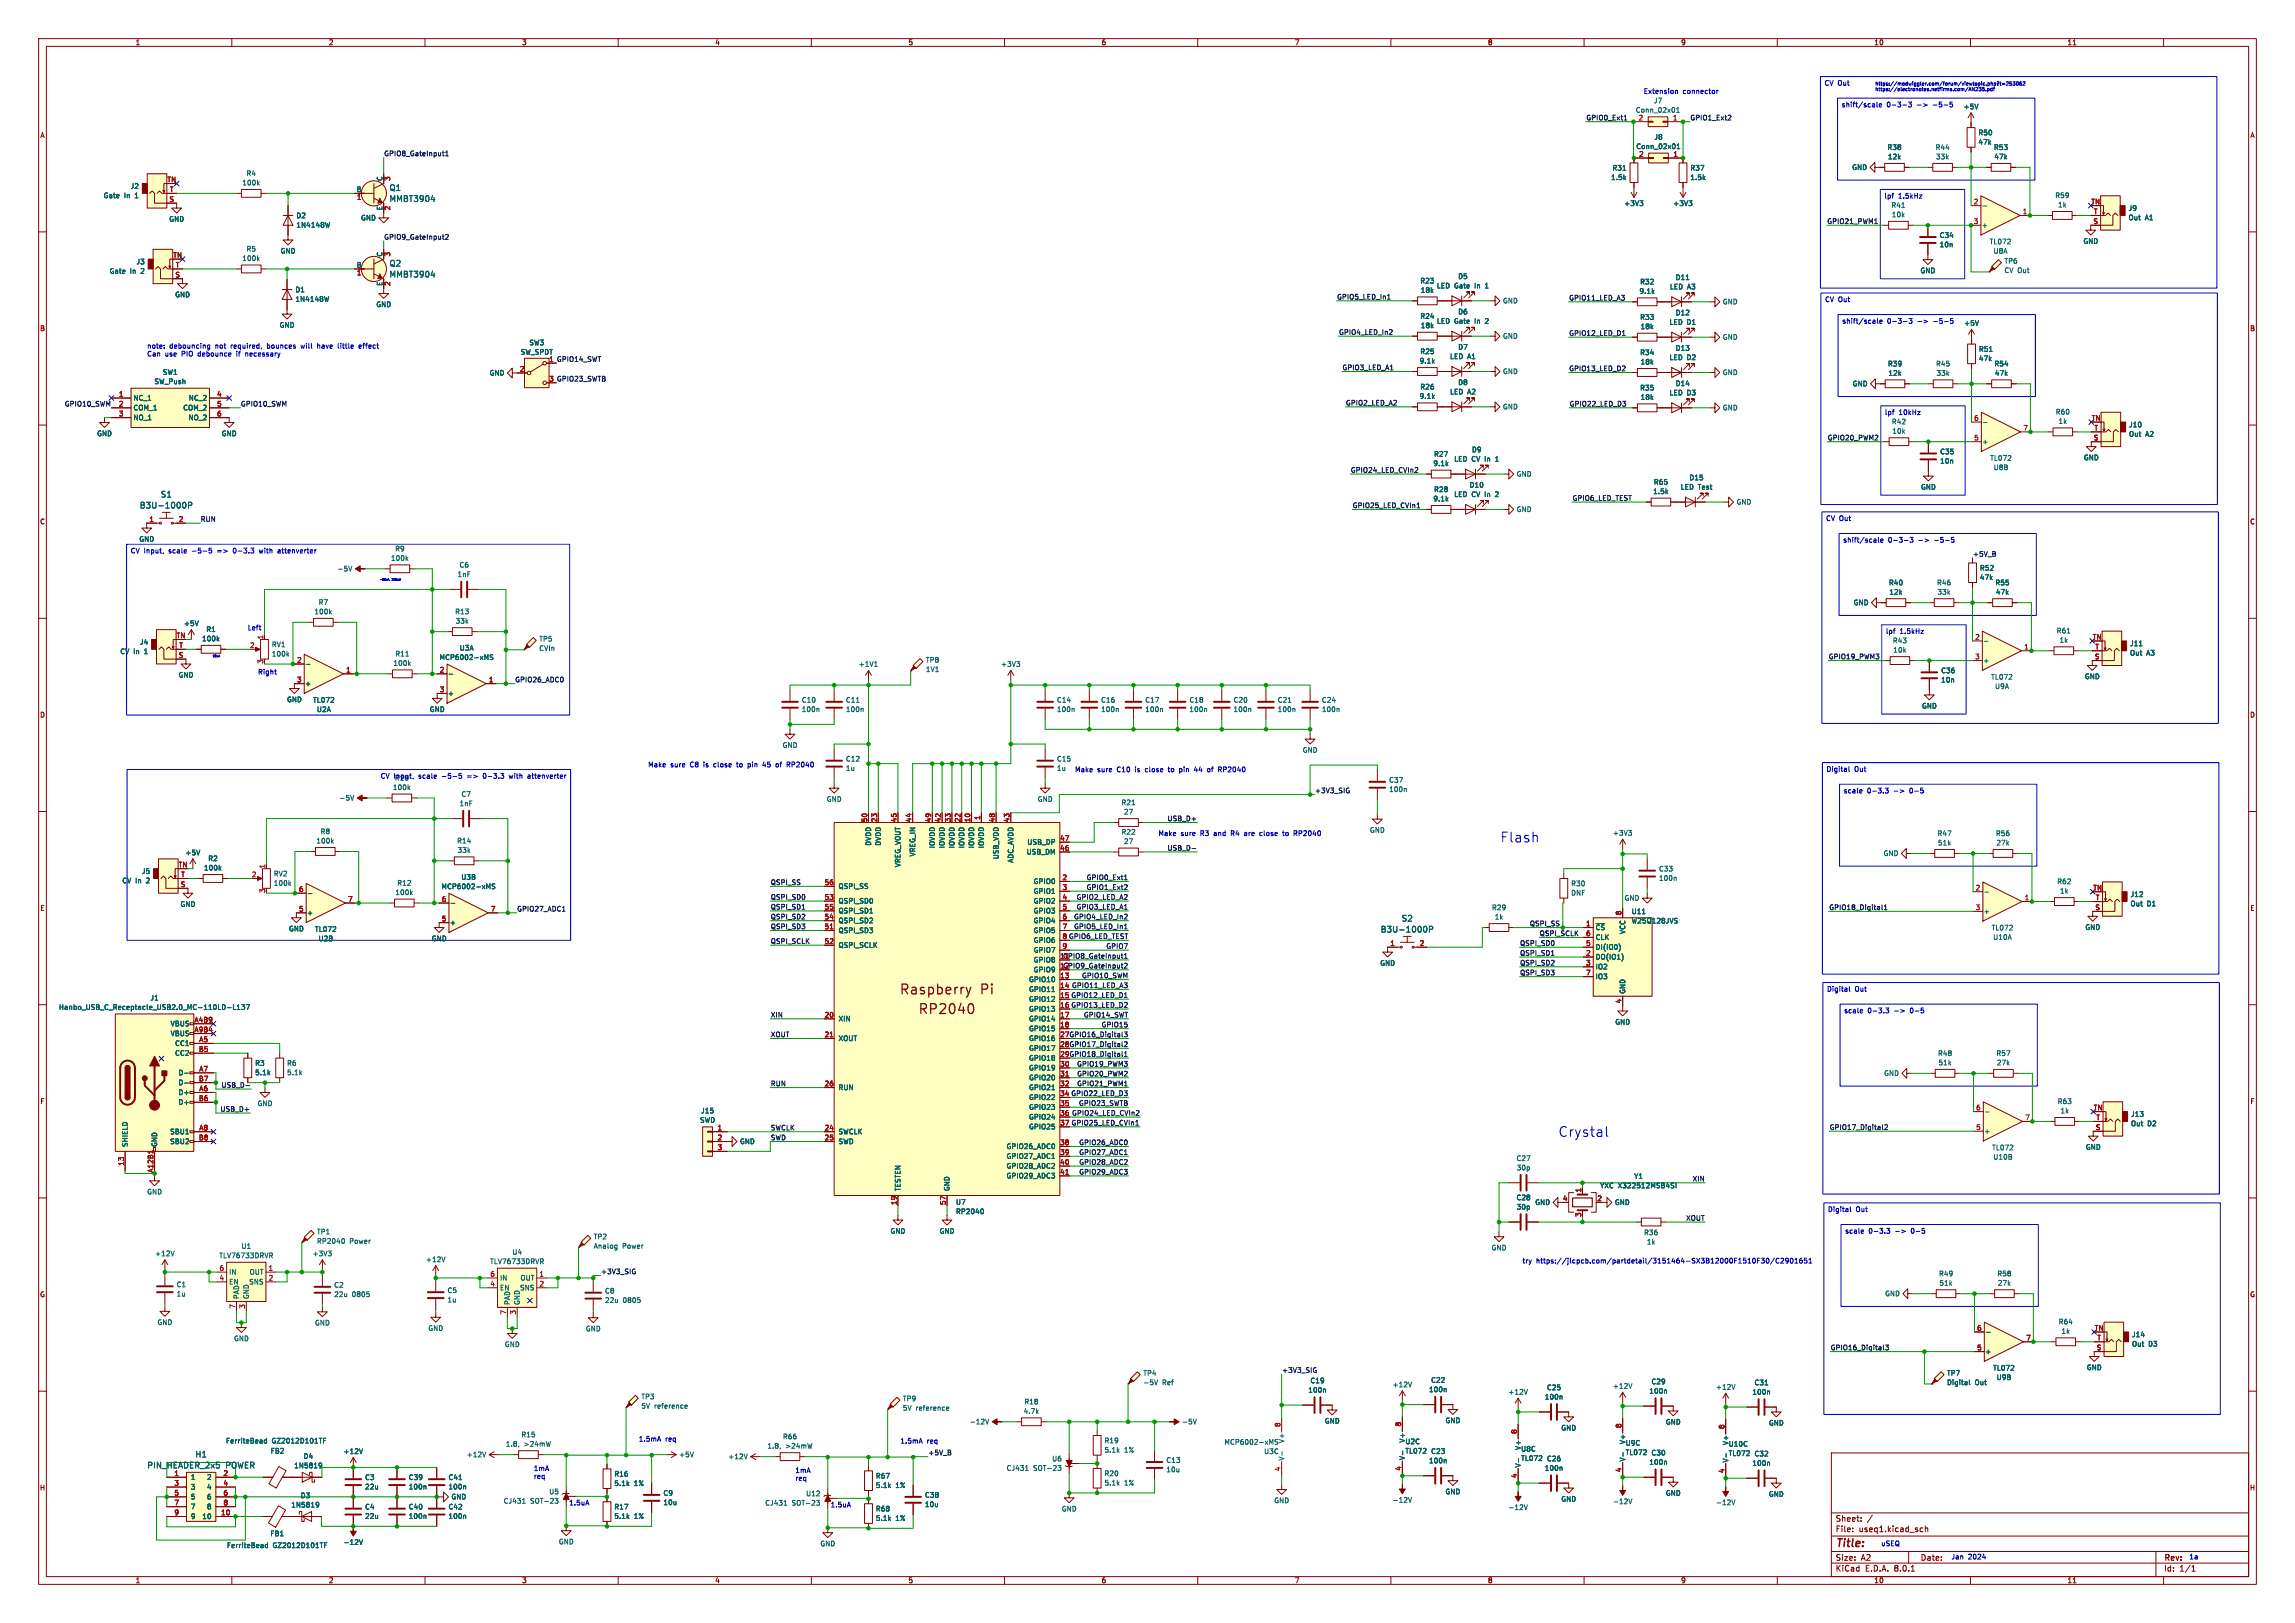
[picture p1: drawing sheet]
<svg xmlns="http://www.w3.org/2000/svg" width="594mm" height="420mm" viewBox="0 0 594 420" stroke-linecap="round" stroke-linejoin="round" font-family="sans-serif">
<defs><g id="words">
<g font-size="3.5" fill="#0000c2">
<text x="388.2" y="218.2">Flash</text>
<text x="403.2" y="294.4">Crystal</text>
</g>
<g font-size="3.5" fill="#840000">
<text x="232.7" y="257.8">Raspberry</text>
<text x="253.8" y="257.8">Pi</text>
<text x="237.5" y="262.9">RP2040</text>
</g>
<text font-size="2.8" fill="#840000" x="475" y="400.9">Title:</text>
<g font-size="2.1" fill="#006464">
<text x="100.7" y="49.6">Q1</text>
<text x="100.7" y="52.4">MMBT3904</text>
<text x="100.7" y="69.2">Q2</text>
<text x="100.7" y="72">MMBT3904</text>
<text x="36.1" y="131.8">B3U-1000P</text>
<text x="41.5" y="128.9">S1</text>
<text x="362.7" y="238.7">S2</text>
<text x="357.3" y="241.5">B3U-1000P</text>
<text x="50.5" y="377.4">H1</text>
<text x="38" y="380.2">PIN_HEADER_2x5</text>
<text x="58.4" y="380.2">POWER</text>
</g>
<g font-size="2.1" fill="#840000">
<text x="475" y="394">Sheet:</text>
<text x="475" y="396.7">File:</text>
<text x="481.1" y="396.7">useq1.kicad_sch</text>
<text x="475" y="406.9">KiCad</text>
<text x="475" y="404.1">Size:</text>
<text x="481.7" y="404.1">A2</text>
<text x="482.7" y="406.9">E.D.A.</text>
<text x="490.3" y="406.9">8.0.1</text>
<text x="497" y="404.1">Date:</text>
<text x="560" y="404.3">Rev:</text>
<text x="560" y="406.9">Id:</text>
<text x="564.1" y="406.9">1/1</text>
</g>
<g font-size="1.8" fill="#840000">
<text x="35" y="11.9">1</text>
<text x="85" y="11.9">2</text>
<text x="135" y="11.9">3</text>
<text x="185" y="11.9">4</text>
<text x="235" y="11.9">5</text>
<text x="285" y="11.9">6</text>
<text x="335" y="11.9">7</text>
<text x="385" y="11.9">8</text>
<text x="435" y="11.9">9</text>
<text x="485" y="11.9">10</text>
<text x="535" y="11.9">11</text>
<text x="10.3" y="35.9">A</text>
<text x="582.3" y="35.9">A</text>
<text x="10.3" y="85.9">B</text>
<text x="582.3" y="85.9">B</text>
<text x="10.3" y="135.9">C</text>
<text x="582.3" y="135.9">C</text>
<text x="10.3" y="185.9">D</text>
<text x="582.3" y="185.9">D</text>
<text x="10.3" y="235.9">E</text>
<text x="582.3" y="235.9">E</text>
<text x="274.3" y="255.8">14 GPIO11_LED_A3</text>
<text x="274.3" y="258.3">15 GPIO12_LED_D1</text>
<text x="274.3" y="260.9">16 GPIO13_LED_D2</text>
<text x="274.3" y="268.5">27 GPIO16_Digital3</text>
<text x="274.3" y="271">28 GPIO17_Digital2</text>
<text x="274.3" y="273.6">29 GPIO18_Digital1</text>
<text x="10.3" y="285.9">F</text>
<text x="274.3" y="283.7">34 GPIO22_LED_D3</text>
<text x="582.3" y="285.9">F</text>
<text x="274.3" y="288.8">36 GPIO24_LED_CVIn2</text>
<text x="274.3" y="291.3">37 GPIO25_LED_CVIn1</text>
<text x="10.3" y="335.9">G</text>
<text x="582.3" y="335.9">G</text>
<text x="10.2" y="385.9">H</text>
<text x="582.2" y="385.9">H</text>
<text x="35" y="409.9">1</text>
<text x="85" y="409.9">2</text>
<text x="135" y="409.9">3</text>
<text x="185" y="409.9">4</text>
<text x="235" y="409.9">5</text>
<text x="285" y="409.9">6</text>
<text x="335" y="409.9">7</text>
<text x="385" y="409.9">8</text>
<text x="435" y="409.9">9</text>
<text x="485" y="409.9">10</text>
<text x="535" y="409.9">11</text>
</g>
<g font-size="1.8" fill="#0000c2">
<text x="472.1" y="22.5">CV Out</text>
<text x="425.3" y="24.4">Extension</text>
<text x="435.6" y="24.4">connector</text>
<text x="476.6" y="28.1">shift/scale</text>
<text x="488.3" y="28.1">0-3-3</text>
<text x="500.6" y="28.1">-5-5</text>
<text x="487.6" y="51.7">lpf</text>
<text x="491.3" y="51.7">1.5kHz</text>
<text x="472.2" y="78.5">CV Out</text>
<text x="476.7" y="84.1">shift/scale</text>
<text x="488.4" y="84.1">0-3-3</text>
<text x="500.7" y="84.1">-5-5</text>
<text x="38" y="90.3">note:</text>
<text x="38" y="92.3">Can</text>
<text x="42.7" y="92.3">use</text>
<text x="43.9" y="90.3">debouncing</text>
<text x="47.1" y="92.3">PIO</text>
<text x="51.5" y="92.3">debounce</text>
<text x="55.9" y="90.3">not</text>
<text x="60.1" y="90.3">required,</text>
<text x="61.7" y="92.3">if</text>
<text x="64.2" y="92.3">necessary</text>
<text x="69.6" y="90.3">bounces</text>
<text x="78.6" y="90.3">will</text>
<text x="83" y="90.3">have</text>
<text x="88.6" y="90.3">little</text>
<text x="94.2" y="90.3">effect</text>
<text x="487.7" y="107.7">lpf</text>
<text x="491.5" y="107.7">10kHz</text>
<text x="472.5" y="135.1">CV Out</text>
<text x="33.7" y="143.5">CV Input,</text>
<text x="43.8" y="143.5">scale</text>
<text x="50" y="143.5">-5-5</text>
<text x="56.7" y="143.5">=&gt;</text>
<text x="61" y="143.5">0-3.3</text>
<text x="68" y="143.5">with</text>
<text x="73" y="143.5">attenverter</text>
<text x="476.9" y="140.7">shift/scale</text>
<text x="488.7" y="140.7">0-3-3</text>
<text x="501" y="140.7">-5-5</text>
<text x="64" y="163.2">Left</text>
<text x="488" y="164.4">lpf</text>
<text x="491.7" y="164.4">1.5kHz</text>
<text x="66.7" y="174.6">Right</text>
<text x="98.4" y="201.8">CV Input,</text>
<text x="102.1" y="202.2">R10</text>
<text x="108.5" y="201.8">scale</text>
<text x="114.7" y="201.8">-5-5</text>
<text x="121.4" y="201.8">=&gt;</text>
<text x="125.7" y="201.8">0-3.3</text>
<text x="132.7" y="201.8">with</text>
<text x="137.7" y="201.8">attenverter</text>
<text x="167.6" y="198.6">Make</text>
<text x="173.5" y="198.6">sure</text>
<text x="178.8" y="198.6">C8</text>
<text x="182.4" y="198.6">is</text>
<text x="185.2" y="198.6">close</text>
<text x="191.4" y="198.6">to</text>
<text x="194.4" y="198.6">pin</text>
<text x="198.5" y="198.6">45</text>
<text x="202.1" y="198.6">of</text>
<text x="205.1" y="198.6">RP2040</text>
<text x="278.1" y="199.9">Make</text>
<text x="284" y="199.9">sure</text>
<text x="289.2" y="199.9">C10</text>
<text x="294.1" y="199.9">is</text>
<text x="296.9" y="199.9">close</text>
<text x="303.1" y="199.9">to</text>
<text x="306.1" y="199.9">pin</text>
<text x="310.2" y="199.9">44</text>
<text x="313.8" y="199.9">of</text>
<text x="316.8" y="199.9">RP2040</text>
<text x="472.6" y="200">Digital</text>
<text x="480" y="200">Out</text>
<text x="477.1" y="205.6">scale</text>
<text x="483.3" y="205.6">0-3.3</text>
<text x="494.6" y="205.6">0-5</text>
<text x="299.7" y="216.4">Make</text>
<text x="305.6" y="216.4">sure</text>
<text x="310.8" y="216.4">R3</text>
<text x="314.5" y="216.4">and</text>
<text x="319.1" y="216.4">R4</text>
<text x="322.8" y="216.4">are</text>
<text x="326.9" y="216.4">close</text>
<text x="333.1" y="216.4">to</text>
<text x="336.2" y="216.4">RP2040</text>
<text x="472.8" y="256.9">Digital</text>
<text x="480.1" y="256.9">Out</text>
<text x="477.2" y="262.5">scale</text>
<text x="483.4" y="262.5">0-3.3</text>
<text x="494.7" y="262.5">0-5</text>
<text x="473" y="314">Digital</text>
<text x="480.3" y="314">Out</text>
<text x="477.5" y="319.5">scale</text>
<text x="483.6" y="319.5">0-3.3</text>
<text x="494.9" y="319.5">0-5</text>
<text x="394" y="327">try</text>
<text x="397.6" y="327">https://jlcpcb.com/partdetail/3151464-SX3B12000F1510F30/C2901651</text>
<text x="165.2" y="373.1">1.5mA</text>
<text x="172.2" y="373.1">req</text>
<text x="232.9" y="373.6">1.5mA</text>
<text x="239.9" y="373.6">req</text>
<text x="138" y="380.7">1mA</text>
<text x="138" y="382.8">req</text>
<text x="205.7" y="381.2">1mA</text>
<text x="205.7" y="383.3">req</text>
<text x="147.2" y="389.6">1.5uA</text>
<text x="214.9" y="390.1">1.5uA</text>
<text x="486.8" y="400.2">uSEQ</text>
<text x="505" y="403.6">Jan</text>
<text x="509.4" y="403.6">2024</text>
<text x="566.5" y="403.6">1a</text>
</g>
<g font-size="1.8" fill="#006464">
<text x="423.3" y="29.4">Conn_02x01</text>
<text x="427.9" y="26.9">J7</text>
<text x="508.1" y="28.5">+5V</text>
<text x="511.9" y="35.2">R50</text>
<text x="423.4" y="38.8">Conn_02x01</text>
<text x="428.1" y="36.3">J8</text>
<text x="488.4" y="39">R38</text>
<text x="488.5" y="41.4">12k</text>
<text x="500.8" y="39">R44</text>
<text x="501" y="41.4">33k</text>
<text x="511.9" y="37.6">47k</text>
<text x="516" y="39">R53</text>
<text x="516.1" y="41.4">47k</text>
<text x="63.7" y="45.7">R4</text>
<text x="99.1" y="47" transform="rotate(-90 99.1 47)">C</text>
<text x="416.9" y="46.8">1.5k</text>
<text x="417.2" y="44.4">R31</text>
<text x="437.4" y="44.4">R37</text>
<text x="437.4" y="46.8">1.5k</text>
<text x="479.3" y="44.2">GND</text>
<text x="26.7" y="51.5">Gate</text>
<text x="32.1" y="51.5">In</text>
<text x="33.7" y="49.1">J2</text>
<text x="35.1" y="51.5">1</text>
<text x="62.6" y="48.2">100k</text>
<text x="92.2" y="49.8">B</text>
<text x="420.3" y="53.5">+3V3</text>
<text x="433" y="53.5">+3V3</text>
<text x="489.4" y="54">R41</text>
<text x="531.8" y="51.5">R59</text>
<text x="532.6" y="53.9">1k</text>
<text x="43.7" y="57.6">GND</text>
<text x="76.6" y="56.7">D2</text>
<text x="76.6" y="59.1">1N4148W</text>
<text x="93.3" y="57.3">GND</text>
<text x="99.1" y="54.5" transform="rotate(-90 99.1 54.5)">E</text>
<text x="489.5" y="56.4">10k</text>
<text x="512.8" y="59.2">+</text>
<text x="550.8" y="54.8">J9</text>
<text x="550.8" y="57.2">Out</text>
<text x="555.2" y="57.2">A1</text>
<text x="63.7" y="65.3">R5</text>
<text x="72.5" y="65.8">GND</text>
<text x="501.9" y="61.8">C34</text>
<text x="501.9" y="64.2">10n</text>
<text x="514.9" y="63.4">TL072</text>
<text x="515.9" y="65.8">U8A</text>
<text x="539.1" y="63.3">GND</text>
<text x="28.2" y="71">Gate</text>
<text x="33.7" y="71">In</text>
<text x="35.2" y="68.6">J3</text>
<text x="36.6" y="71">2</text>
<text x="62.6" y="67.7">100k</text>
<text x="92.2" y="69.3">B</text>
<text x="99.1" y="66.5" transform="rotate(-90 99.1 66.5)">C</text>
<text x="496.9" y="70.9">GND</text>
<text x="518.7" y="68.4">TP6</text>
<text x="518.7" y="70.8">CV Out</text>
<text x="45.2" y="77.1">GND</text>
<text x="76.3" y="75.9">D1</text>
<text x="99.1" y="74.1" transform="rotate(-90 99.1 74.1)">E</text>
<text x="367.5" y="73.6">R23</text>
<text x="367.6" y="76">18k</text>
<text x="371.8" y="74.8">LED Gate</text>
<text x="377.3" y="72.4">D5</text>
<text x="381.8" y="74.8">In</text>
<text x="384.7" y="74.8">1</text>
<text x="424.2" y="76.2">9.1k</text>
<text x="424.4" y="73.8">R32</text>
<text x="432.1" y="75.1">LED A3</text>
<text x="433.6" y="72.7">D11</text>
<text x="76.3" y="78.3">1N4148W</text>
<text x="97.3" y="79.7">GND</text>
<text x="367.5" y="82.7">R24</text>
<text x="371.8" y="84">LED Gate</text>
<text x="377.3" y="81.6">D6</text>
<text x="381.8" y="84">In</text>
<text x="384.7" y="84">2</text>
<text x="388.9" y="78.7">GND</text>
<text x="424.4" y="83">R33</text>
<text x="433.6" y="81.8">D12</text>
<text x="445.8" y="79">GND</text>
<text x="72.3" y="85">GND</text>
<text x="136.9" y="89.6">SW3</text>
<text x="367.6" y="85.1">18k</text>
<text x="388.9" y="87.9">GND</text>
<text x="424.5" y="85.4">18k</text>
<text x="432" y="84.2">LED D1</text>
<text x="445.8" y="88.1">GND</text>
<text x="508.2" y="84.5">+5V</text>
<text x="134.7" y="92">SW_SPDT</text>
<text x="367.3" y="94.3">9.1k</text>
<text x="367.5" y="91.8">R25</text>
<text x="375.2" y="93.1">LED A1</text>
<text x="377.3" y="90.7">D7</text>
<text x="424.4" y="92.1">R34</text>
<text x="424.5" y="94.5">18k</text>
<text x="432" y="93.4">LED D2</text>
<text x="433.6" y="91">D13</text>
<text x="488.5" y="95">R39</text>
<text x="501" y="95">R45</text>
<text x="512.1" y="91.2">R51</text>
<text x="512.1" y="93.6">47k</text>
<text x="516.1" y="95">R54</text>
<text x="39.9" y="99.6">SW_Push</text>
<text x="42" y="97.2">SW1</text>
<text x="126.6" y="97.4">GND</text>
<text x="367.5" y="101">R26</text>
<text x="377.3" y="99.8">D8</text>
<text x="388.9" y="97">GND</text>
<text x="424.4" y="101.2">R35</text>
<text x="433.6" y="100.1">D14</text>
<text x="445.8" y="97.3">GND</text>
<text x="479.4" y="100.2">GND</text>
<text x="488.6" y="97.4">12k</text>
<text x="501.1" y="97.4">33k</text>
<text x="516.2" y="97.4">47k</text>
<text x="34.4" y="103.9">NC_1</text>
<text x="34.4" y="106.4">COM_1</text>
<text x="47.3" y="106.4">COM_2</text>
<text x="48.7" y="103.9">NC_2</text>
<text x="367.3" y="103.4">9.1k</text>
<text x="375.2" y="102.3">LED A2</text>
<text x="388.9" y="106.1">GND</text>
<text x="424.5" y="103.7">18k</text>
<text x="432" y="102.5">LED D3</text>
<text x="445.8" y="106.4">GND</text>
<text x="532" y="107.5">R60</text>
<text x="25" y="113.1">GND</text>
<text x="34.4" y="108.9">NO_1</text>
<text x="48.7" y="108.9">NO_2</text>
<text x="57.3" y="113.1">GND</text>
<text x="489.5" y="110">R42</text>
<text x="489.7" y="112.4">10k</text>
<text x="532.7" y="109.9">1k</text>
<text x="550.9" y="110.8">J10</text>
<text x="550.9" y="113.2">Out</text>
<text x="555.3" y="113.2">A2</text>
<text x="371.1" y="118.4">R27</text>
<text x="376.3" y="119.7">LED CV In</text>
<text x="380.9" y="117.2">D9</text>
<text x="387.3" y="119.7">1</text>
<text x="502" y="117.8">C35</text>
<text x="513" y="115.2">+</text>
<text x="515" y="119.4">TL072</text>
<text x="539.2" y="119.3">GND</text>
<text x="370.9" y="120.8">9.1k</text>
<text x="392.4" y="123.5">GND</text>
<text x="427.9" y="125.6">R65</text>
<text x="437.2" y="124.5">D15</text>
<text x="502" y="120.2">10n</text>
<text x="515.9" y="121.8">U8B</text>
<text x="370.9" y="130">9.1k</text>
<text x="371.1" y="127.5">R28</text>
<text x="376.3" y="128.8">LED CV In</text>
<text x="380.3" y="126.4">D10</text>
<text x="387.3" y="128.8">2</text>
<text x="427.8" y="128">1.5k</text>
<text x="434.9" y="126.9">LED Test</text>
<text x="449.3" y="130.8">GND</text>
<text x="497.1" y="126.9">GND</text>
<text x="392.4" y="132.7">GND</text>
<text x="35.9" y="140.4">GND</text>
<text x="102.2" y="142.9">R9</text>
<text x="87.2" y="148.1">-5V</text>
<text x="101.1" y="145.3">100k</text>
<text x="118.3" y="149.5">1nF</text>
<text x="118.8" y="147.1">C6</text>
<text x="512.3" y="147.9">R52</text>
<text x="488.8" y="151.7">R40</text>
<text x="488.9" y="154.1">12k</text>
<text x="501.2" y="151.7">R46</text>
<text x="501.3" y="154.1">33k</text>
<text x="512.3" y="150.3">47k</text>
<text x="516.3" y="151.7">R55</text>
<text x="516.5" y="154.1">47k</text>
<text x="81.3" y="159.2">100k</text>
<text x="82.4" y="156.7">R7</text>
<text x="117.7" y="159.2">R13</text>
<text x="117.8" y="161.6">33k</text>
<text x="479.7" y="156.8">GND</text>
<text x="36.1" y="167">J4</text>
<text x="47.5" y="162.2">+5V</text>
<text x="52.2" y="166.1">100k</text>
<text x="53.3" y="163.7">R1</text>
<text x="70.2" y="167.7">RV1</text>
<text x="139.5" y="166.2">TP5</text>
<text x="489.8" y="166.6">R43</text>
<text x="532.2" y="164.1">R61</text>
<text x="532.9" y="166.5">1k</text>
<text x="551.2" y="167.4">J11</text>
<text x="31" y="169.5">CV In</text>
<text x="37.5" y="169.5">1</text>
<text x="70.2" y="170.1">100k</text>
<text x="101.7" y="172.5">100k</text>
<text x="102.2" y="170.1">R11</text>
<text x="113.6" y="171">MCP6002-xMS</text>
<text x="118.9" y="168.6">U3A</text>
<text x="139.5" y="168.6">CVIn</text>
<text x="222.1" y="172.8">+1V1</text>
<text x="239.5" y="171.7">TP8</text>
<text x="259" y="172.8">+3V3</text>
<text x="489.9" y="169.1">10k</text>
<text x="513.2" y="171.8">+</text>
<text x="551.2" y="169.8">Out</text>
<text x="555.6" y="169.8">A3</text>
<text x="46.1" y="175.6">GND</text>
<text x="78.9" y="177.8">+</text>
<text x="239.5" y="174.1">1V1</text>
<text x="502.3" y="174.4">C36</text>
<text x="502.3" y="176.8">10n</text>
<text x="515.2" y="176.1">TL072</text>
<text x="516.2" y="178.5">U9A</text>
<text x="539.5" y="175.9">GND</text>
<text x="74.2" y="181.9">GND</text>
<text x="80.9" y="182">TL072</text>
<text x="81.9" y="184.5">U2A</text>
<text x="111.1" y="184.4">GND</text>
<text x="115.8" y="180.3">+</text>
<text x="207.4" y="184.4">100n</text>
<text x="207.4" y="182">C10</text>
<text x="218.8" y="184.4">100n</text>
<text x="218.8" y="182">C11</text>
<text x="273.4" y="182">C14</text>
<text x="273.4" y="184.4">100n</text>
<text x="284.9" y="182">C16</text>
<text x="284.9" y="184.4">100n</text>
<text x="296.3" y="182">C17</text>
<text x="296.3" y="184.4">100n</text>
<text x="307.7" y="182">C18</text>
<text x="307.7" y="184.4">100n</text>
<text x="319.2" y="182">C20</text>
<text x="319.2" y="184.4">100n</text>
<text x="330.6" y="182">C21</text>
<text x="330.6" y="184.4">100n</text>
<text x="342" y="182">C24</text>
<text x="342" y="184.4">100n</text>
<text x="497.3" y="183.6">GND</text>
<text x="202.4" y="193.7">GND</text>
<text x="218.8" y="197.3">C12</text>
<text x="273.4" y="197.3">C15</text>
<text x="337.1" y="195">GND</text>
<text x="218.8" y="199.7">1u</text>
<text x="273.4" y="199.7">1u</text>
<text x="359.4" y="202.7">C37</text>
<text x="87.7" y="207.4">-5V</text>
<text x="101.6" y="204.6">100k</text>
<text x="118.8" y="208.8">1nF</text>
<text x="119.3" y="206.4">C7</text>
<text x="213.9" y="207.7">GND</text>
<text x="268.5" y="207.7">GND</text>
<text x="290.2" y="208.6">R21</text>
<text x="359.4" y="205.1">100n</text>
<text x="290.8" y="211">27</text>
<text x="354.5" y="215.7">GND</text>
<text x="47.9" y="221.5">+5V</text>
<text x="81.8" y="218.5">100k</text>
<text x="82.9" y="216">R8</text>
<text x="118.2" y="218.5">R14</text>
<text x="118.3" y="220.9">33k</text>
<text x="225.7" y="219" transform="rotate(-90 225.7 219)">DVDD</text>
<text x="228.2" y="219" transform="rotate(-90 228.2 219)">DVDD</text>
<text x="237.1" y="221.8" transform="rotate(-90 237.1 221.8)">VREG_IN</text>
<text x="242.2" y="219.6" transform="rotate(-90 242.2 219.6)">IOVDD</text>
<text x="244.7" y="219.6" transform="rotate(-90 244.7 219.6)">IOVDD</text>
<text x="247.2" y="219.6" transform="rotate(-90 247.2 219.6)">IOVDD</text>
<text x="249.8" y="219.6" transform="rotate(-90 249.8 219.6)">IOVDD</text>
<text x="252.3" y="219.6" transform="rotate(-90 252.3 219.6)">IOVDD</text>
<text x="254.9" y="219.6" transform="rotate(-90 254.9 219.6)">IOVDD</text>
<text x="265.6" y="221.3">USB_DM</text>
<text x="265.8" y="218.8">USB_DP</text>
<text x="290.2" y="216.2">R22</text>
<text x="290.8" y="218.6">27</text>
<text x="417.3" y="216.4">+3V3</text>
<text x="487.4" y="221.7">GND</text>
<text x="501.4" y="216.6">R47</text>
<text x="501.5" y="219">51k</text>
<text x="516.5" y="216.6">R56</text>
<text x="516.6" y="219">27k</text>
<text x="36.6" y="226.3">J5</text>
<text x="52.7" y="225.5">100k</text>
<text x="53.8" y="223">R2</text>
<text x="70.7" y="227">RV2</text>
<text x="119.3" y="227.9">U3B</text>
<text x="233.3" y="224.5" transform="rotate(-90 233.3 224.5)">VREG_VOUT</text>
<text x="258.7" y="222.5" transform="rotate(-90 258.7 222.5)">USB_VDD</text>
<text x="262.5" y="223.4" transform="rotate(-90 262.5 223.4)">ADC_AVDD</text>
<text x="429.3" y="225.7">C33</text>
<text x="31.5" y="228.8">CV In</text>
<text x="38" y="228.8">2</text>
<text x="70.7" y="229.4">100k</text>
<text x="102.2" y="231.8">100k</text>
<text x="102.7" y="229.4">R12</text>
<text x="114.1" y="230.3">MCP6002-xMS</text>
<text x="216.9" y="230.2">QSPI_SS</text>
<text x="267.4" y="229">GPIO0</text>
<text x="267.4" y="231.5">GPIO1</text>
<text x="406.5" y="229.5">R30</text>
<text x="406.5" y="231.9">DNF</text>
<text x="420.3" y="233.3">GND</text>
<text x="429.3" y="228.1">100n</text>
<text x="532.3" y="229">R62</text>
<text x="533.1" y="231.4">1k</text>
<text x="551.3" y="232.3">J12</text>
<text x="46.6" y="234.9">GND</text>
<text x="79.4" y="237.1">+</text>
<text x="116.3" y="239.6">+</text>
<text x="216.9" y="234">QSPI_SD0</text>
<text x="216.9" y="239.1">QSPI_SD2</text>
<text x="216.9" y="236.6">QSPI_SD1</text>
<text x="267.4" y="234">GPIO2</text>
<text x="267.4" y="236.6">GPIO3</text>
<text x="267.4" y="239.1">GPIO4</text>
<text x="386" y="235.7">R29</text>
<text x="386.8" y="238.2">1k</text>
<text x="422.2" y="236.7">U11</text>
<text x="422.2" y="239.2">W25Q128JVS</text>
<text x="513.3" y="236.7">+</text>
<text x="551.3" y="234.7">Out</text>
<text x="555.7" y="234.7">D1</text>
<text x="74.7" y="241.2">GND</text>
<text x="81.4" y="241.3">TL072</text>
<text x="82.3" y="243.8">U2B</text>
<text x="111.6" y="243.8">GND</text>
<text x="216.9" y="241.7">QSPI_SD3</text>
<text x="216.9" y="245.5">QSPI_SCLK</text>
<text x="267.4" y="241.7">GPIO5</text>
<text x="267.4" y="244.2">GPIO6</text>
<text x="412.9" y="240.9">~{CS}</text>
<text x="412.9" y="246">DI(IO0)</text>
<text x="412.9" y="243.4">CLK</text>
<text x="420.9" y="241.8" transform="rotate(-90 420.9 241.8)">VCC</text>
<text x="515.4" y="241">TL072</text>
<text x="515.8" y="243.4">U10A</text>
<text x="539.6" y="240.8">GND</text>
<text x="267.4" y="249.3">GPIO8</text>
<text x="267.4" y="251.8">GPIO9</text>
<text x="267.4" y="246.7">GPIO7</text>
<text x="357.1" y="250.1">GND</text>
<text x="412.9" y="248.5">DO(IO1)</text>
<text x="412.9" y="251.1">IO2</text>
<text x="266.2" y="254.4">GPIO10</text>
<text x="266.2" y="256.9">GPIO11</text>
<text x="412.9" y="253.6">IO3</text>
<text x="420.9" y="257.3" transform="rotate(-90 420.9 257.3)">GND</text>
<text x="15.1" y="261.5">Hanbo_USB_C_Receptacle_USB2.0_MC-110LD-L137</text>
<text x="38.8" y="259.1">J1</text>
<text x="266.2" y="259.4">GPIO12</text>
<text x="266.2" y="262">GPIO13</text>
<text x="44" y="265.8">VBUS</text>
<text x="44" y="268.3">VBUS</text>
<text x="216.9" y="264.5">XIN</text>
<text x="216.9" y="269.6">XOUT</text>
<text x="266.2" y="264.5">GPIO14</text>
<text x="266.2" y="267.1">GPIO15</text>
<text x="266.2" y="269.6">GPIO16</text>
<text x="418" y="265.3">GND</text>
<text x="45.2" y="270.9">CC1</text>
<text x="45.2" y="273.4">CC2</text>
<text x="266.2" y="272.1">GPIO17</text>
<text x="266.2" y="274.7">GPIO18</text>
<text x="501.5" y="273.5">R48</text>
<text x="501.6" y="275.9">51k</text>
<text x="516.6" y="273.5">R57</text>
<text x="516.7" y="275.9">27k</text>
<text x="46.1" y="278.5">D-</text>
<text x="46.1" y="281">D-</text>
<text x="65.9" y="276">R3</text>
<text x="65.9" y="278.4">5.1k</text>
<text x="74.2" y="276">R6</text>
<text x="74.2" y="278.4">5.1k</text>
<text x="266.2" y="277.2">GPIO19</text>
<text x="266.2" y="279.8">GPIO20</text>
<text x="487.5" y="278.6">GND</text>
<text x="46.1" y="283.6">D+</text>
<text x="46.1" y="286.1">D+</text>
<text x="66.5" y="286.4">GND</text>
<text x="216.9" y="282.3">RUN</text>
<text x="266.2" y="282.3">GPIO21</text>
<text x="266.2" y="284.8">GPIO22</text>
<text x="266.2" y="287.4">GPIO23</text>
<text x="532.5" y="285.9">R63</text>
<text x="43.9" y="293.7">SBU1</text>
<text x="181.1" y="290.7">SWD</text>
<text x="181.3" y="288.3">J15</text>
<text x="216.9" y="293.7">SWCLK</text>
<text x="266.2" y="289.9">GPIO24</text>
<text x="266.2" y="292.5">GPIO25</text>
<text x="513.5" y="293.6">+</text>
<text x="533.2" y="288.3">1k</text>
<text x="551.4" y="289.2">J13</text>
<text x="551.4" y="291.6">Out</text>
<text x="555.8" y="291.6">D2</text>
<text x="33.2" y="296.9" transform="rotate(-90 33.2 296.9)">SHIELD</text>
<text x="40.9" y="296.9" transform="rotate(-90 40.9 296.9)">GND</text>
<text x="43.9" y="296.3">SBU2</text>
<text x="191.4" y="296.3">GND</text>
<text x="216.9" y="296.3">SWD</text>
<text x="260.4" y="297.5">GPIO26_ADC0</text>
<text x="515.5" y="297.9">TL072</text>
<text x="539.7" y="297.7">GND</text>
<text x="260.4" y="300.1">GPIO27_ADC1</text>
<text x="260.4" y="302.6">GPIO28_ADC2</text>
<text x="260.4" y="305.2">GPIO29_ADC3</text>
<text x="392.4" y="300.6">C27</text>
<text x="392.5" y="303.1">30p</text>
<text x="422.9" y="305.3">Y1</text>
<text x="515.8" y="300.3">U10B</text>
<text x="38" y="309.3">GND</text>
<text x="233.3" y="308.4" transform="rotate(-90 233.3 308.4)">TESTEN</text>
<text x="246" y="308.4" transform="rotate(-90 246 308.4)">GND</text>
<text x="247.3" y="312">U7</text>
<text x="392.4" y="310.8">C28</text>
<text x="414" y="307.7">YXC X322512MSB4SI</text>
<text x="247.3" y="314.4">RP2040</text>
<text x="392.5" y="313.2">30p</text>
<text x="397.2" y="312">GND</text>
<text x="417.8" y="312">GND</text>
<text x="62.4" y="323.4">U1</text>
<text x="81.9" y="319.6">TP1</text>
<text x="81.9" y="322.1">RP2040</text>
<text x="90.5" y="322.1">Power</text>
<text x="153.6" y="320.9">TP2</text>
<text x="153.6" y="323.3">Analog</text>
<text x="161.1" y="323.3">Power</text>
<text x="230.4" y="319.4">GND</text>
<text x="243.1" y="319.4">GND</text>
<text x="385.9" y="323.8">GND</text>
<text x="425.4" y="319.8">R36</text>
<text x="426.1" y="322.3">1k</text>
<text x="40" y="325.3">+12V</text>
<text x="56.6" y="325.8">TLV76733DRVR</text>
<text x="80.8" y="325.3">+3V3</text>
<text x="110.1" y="326.8">+12V</text>
<text x="126.7" y="327.3">TLV76733DRVR</text>
<text x="132.5" y="324.9">U4</text>
<text x="45.6" y="333.3">C1</text>
<text x="45.6" y="335.7">1u</text>
<text x="59.2" y="332.6">EN</text>
<text x="59.2" y="330">IN</text>
<text x="64.4" y="332.6">SNS</text>
<text x="64.5" y="330">OUT</text>
<text x="86.4" y="333.4">C2</text>
<text x="86.4" y="335.8">22u</text>
<text x="91.1" y="335.8">0805</text>
<text x="115.7" y="334.8">C5</text>
<text x="129.3" y="334.1">EN</text>
<text x="129.3" y="331.6">IN</text>
<text x="134.5" y="334.1">SNS</text>
<text x="134.6" y="331.6">OUT</text>
<text x="156.5" y="334.9">C8</text>
<text x="487.8" y="335.6">GND</text>
<text x="501.7" y="330.5">R49</text>
<text x="501.9" y="332.9">51k</text>
<text x="516.8" y="330.5">R58</text>
<text x="517" y="332.9">27k</text>
<text x="62.1" y="336.3" transform="rotate(-90 62.1 336.3)">PAD</text>
<text x="64.6" y="336.3" transform="rotate(-90 64.6 336.3)">GND</text>
<text x="115.7" y="337.2">1u</text>
<text x="132.2" y="337.8" transform="rotate(-90 132.2 337.8)">PAD</text>
<text x="134.7" y="337.8" transform="rotate(-90 134.7 337.8)">GND</text>
<text x="156.5" y="337.4">22u</text>
<text x="161.2" y="337.4">0805</text>
<text x="40.6" y="343.1">GND</text>
<text x="60.4" y="347.3">GND</text>
<text x="81.4" y="343.2">GND</text>
<text x="110.7" y="344.6">GND</text>
<text x="151.5" y="344.7">GND</text>
<text x="532.7" y="342.9">R64</text>
<text x="533.5" y="345.3">1k</text>
<text x="551.7" y="346.2">J14</text>
<text x="130.6" y="348.8">GND</text>
<text x="513.7" y="350.6">+</text>
<text x="551.7" y="348.7">Out</text>
<text x="556.1" y="348.7">D3</text>
<text x="295.8" y="356.2">TP4</text>
<text x="295.8" y="358.6">-5V</text>
<text x="300.8" y="358.6">Ref</text>
<text x="339" y="358.2">C19</text>
<text x="360.3" y="359.2">+12V</text>
<text x="370.3" y="358">C22</text>
<text x="400.3" y="359.9">C25</text>
<text x="417.3" y="359.6">+12V</text>
<text x="427.3" y="358.4">C29</text>
<text x="444" y="359.8">+12V</text>
<text x="454" y="358.7">C31</text>
<text x="503.8" y="356.2">TP7</text>
<text x="503.8" y="358.6">Digital</text>
<text x="511.2" y="358.6">Out</text>
<text x="515.8" y="354.9">TL072</text>
<text x="516.7" y="357.3">U9B</text>
<text x="540" y="354.8">GND</text>
<text x="165.9" y="362.3">TP3</text>
<text x="165.9" y="364.7">5V</text>
<text x="169.3" y="364.7">reference</text>
<text x="233.6" y="362.8">TP9</text>
<text x="233.6" y="365.2">5V</text>
<text x="237" y="365.2">reference</text>
<text x="265" y="363.6">R18</text>
<text x="338.5" y="360.6">100n</text>
<text x="369.7" y="360.5">100n</text>
<text x="390.3" y="361.1">+12V</text>
<text x="399.7" y="362.4">100n</text>
<text x="426.8" y="360.8">100n</text>
<text x="453.4" y="361.1">100n</text>
<text x="250.9" y="368.8">-12V</text>
<text x="264.8" y="366">4.7k</text>
<text x="305.8" y="368.8">-5V</text>
<text x="342.8" y="368.6">GND</text>
<text x="374" y="368.5">GND</text>
<text x="404" y="370.4">GND</text>
<text x="431" y="368.9">GND</text>
<text x="457.7" y="369.1">GND</text>
<text x="58.4" y="373.7">FerriteBead</text>
<text x="69.9" y="376.3">FB2</text>
<text x="70.4" y="373.7">GZ2012D101TF</text>
<text x="78.5" y="377.7">D4</text>
<text x="88.8" y="376.5">+12V</text>
<text x="120.7" y="377.3">+12V</text>
<text x="130.8" y="374.6">1.8,</text>
<text x="134.8" y="372.1">R15</text>
<text x="135.6" y="374.6">&gt;24mW</text>
<text x="175.7" y="377.3">+5V</text>
<text x="188.4" y="377.8">+12V</text>
<text x="198.5" y="375.1">1.8,</text>
<text x="202.5" y="372.6">R66</text>
<text x="203.3" y="375.1">&gt;24mW</text>
<text x="285.8" y="373.7">R19</text>
<text x="285.8" y="376.1">5.1k</text>
<text x="291" y="376.1">1%</text>
<text x="316.8" y="374">MCP6002-xMS</text>
<text x="327.1" y="376.5">U3C</text>
<text x="332.6" y="373.6" transform="rotate(-90 332.6 373.6)">V+</text>
<text x="363.6" y="373.9">U2C</text>
<text x="363.6" y="376.3">TL072</text>
<text x="363.8" y="378" transform="rotate(-90 363.8 378)">V-</text>
<text x="363.8" y="373.5" transform="rotate(-90 363.8 373.5)">V+</text>
<text x="370.3" y="376.4">C23</text>
<text x="393.6" y="375.8">U8C</text>
<text x="393.8" y="375.4" transform="rotate(-90 393.8 375.4)">V+</text>
<text x="420.6" y="374.3">U9C</text>
<text x="420.6" y="376.7">TL072</text>
<text x="420.9" y="373.8" transform="rotate(-90 420.9 373.8)">V+</text>
<text x="427.3" y="376.8">C30</text>
<text x="447.3" y="374.6">U10C</text>
<text x="447.3" y="377">TL072</text>
<text x="447.5" y="374.1" transform="rotate(-90 447.5 374.1)">V+</text>
<text x="454" y="377.1">C32</text>
<text x="49.3" y="383.1">1</text>
<text x="53.5" y="383.1">2</text>
<text x="76" y="380.1">1N5819</text>
<text x="94.4" y="383.2">C3</text>
<text x="105.7" y="383.2">C39</text>
<text x="116" y="383.2">C41</text>
<text x="158.9" y="382.3">R16</text>
<text x="226.6" y="382.8">R67</text>
<text x="260.4" y="380.8">CJ431</text>
<text x="267.4" y="380.8">SOT-23</text>
<text x="272.2" y="378.4">U6</text>
<text x="285.8" y="382.2">R20</text>
<text x="301.8" y="378.7">C13</text>
<text x="301.8" y="381.2">10u</text>
<text x="332.6" y="378.1" transform="rotate(-90 332.6 378.1)">V-</text>
<text x="369.7" y="378.9">100n</text>
<text x="393.6" y="378.2">TL072</text>
<text x="393.8" y="379.9" transform="rotate(-90 393.8 379.9)">V-</text>
<text x="399.7" y="380.8">100n</text>
<text x="400.3" y="378.4">C26</text>
<text x="420.9" y="378.3" transform="rotate(-90 420.9 378.3)">V-</text>
<text x="426.8" y="379.3">100n</text>
<text x="447.5" y="378.6" transform="rotate(-90 447.5 378.6)">V-</text>
<text x="453.4" y="379.5">100n</text>
<text x="49.3" y="385.7">3</text>
<text x="49.3" y="388.2">5</text>
<text x="53.5" y="385.7">4</text>
<text x="53.5" y="388.2">6</text>
<text x="77.7" y="387.9">D3</text>
<text x="94.4" y="385.6">22u</text>
<text x="105.7" y="385.6">100n</text>
<text x="116" y="385.6">100n</text>
<text x="116.7" y="388.2">GND</text>
<text x="130.2" y="389.3">CJ431</text>
<text x="137.3" y="389.3">SOT-23</text>
<text x="142" y="386.9">U5</text>
<text x="158.9" y="384.7">5.1k</text>
<text x="164.1" y="384.7">1%</text>
<text x="171.6" y="387.3">C9</text>
<text x="171.6" y="389.7">10u</text>
<text x="197.9" y="389.8">CJ431</text>
<text x="205" y="389.8">SOT-23</text>
<text x="208.5" y="387.4">U12</text>
<text x="226.6" y="385.2">5.1k</text>
<text x="231.8" y="385.2">1%</text>
<text x="239.3" y="387.8">C38</text>
<text x="285.8" y="384.6">5.1k</text>
<text x="291" y="384.6">1%</text>
<text x="329.7" y="389.2">GND</text>
<text x="360.3" y="389">-12V</text>
<text x="374" y="386.9">GND</text>
<text x="404" y="388.8">GND</text>
<text x="417.3" y="389.4">-12V</text>
<text x="431" y="387.3">GND</text>
<text x="444" y="389.7">-12V</text>
<text x="457.7" y="387.5">GND</text>
<text x="49.3" y="390.8">7</text>
<text x="49.3" y="393.3">9</text>
<text x="52.2" y="393.3">10</text>
<text x="53.5" y="390.8">8</text>
<text x="75.3" y="390.3">1N5819</text>
<text x="94.4" y="390.8">C4</text>
<text x="94.4" y="393.2">22u</text>
<text x="105.7" y="393.2">100n</text>
<text x="105.7" y="390.8">C40</text>
<text x="116" y="393.2">100n</text>
<text x="116" y="390.8">C42</text>
<text x="158.9" y="390.8">R17</text>
<text x="158.9" y="393.2">5.1k</text>
<text x="164.1" y="393.2">1%</text>
<text x="226.6" y="391.3">R68</text>
<text x="226.6" y="393.7">5.1k</text>
<text x="231.8" y="393.7">1%</text>
<text x="239.3" y="390.2">10u</text>
<text x="274.7" y="391.3">GND</text>
<text x="390.3" y="390.9">-12V</text>
<text x="58.6" y="400.8">FerriteBead</text>
<text x="69.9" y="397.7">FB1</text>
<text x="70.6" y="400.8">GZ2012D101TF</text>
<text x="88.8" y="400">-12V</text>
<text x="144.5" y="399.8">GND</text>
<text x="212.2" y="400.3">GND</text>
</g>
<g font-size="1.8" fill="#0f0f0f">
<text x="410.5" y="31.2">GPIO0_Ext1</text>
<text x="437.4" y="31.2">GPIO1_Ext2</text>
<text x="99.3" y="40.5">GPIO8_GateInput1</text>
<text x="472.8" y="58">GPIO21_PWM1</text>
<text x="99.3" y="62.1">GPIO9_GateInput2</text>
<text x="345.9" y="77.6">GPIO5_LED_In1</text>
<text x="406" y="77.8">GPIO11_LED_A3</text>
<text x="346.5" y="86.7">GPIO4_LED_In2</text>
<text x="406" y="87">GPIO12_LED_D1</text>
<text x="142" y="93.7">1 GPIO14_SWT</text>
<text x="347.3" y="95.9">GPIO3_LED_A1</text>
<text x="142" y="98.8">3 GPIO23_SWTB</text>
<text x="406" y="96.1">GPIO13_LED_D2</text>
<text x="16.7" y="105.3">GPIO10_SWM</text>
<text x="62.2" y="105.3">GPIO10_SWM</text>
<text x="348.2" y="105">GPIO2_LED_A2</text>
<text x="406.1" y="105.3">GPIO22_LED_D3</text>
<text x="472.9" y="114">GPIO20_PWM2</text>
<text x="349.5" y="122.4">GPIO24_LED_CVIn2</text>
<text x="350" y="131.6">GPIO25_LED_CVIn1</text>
<text x="406.9" y="129.7">GPIO6_LED_TEST</text>
<text x="51.8" y="135.1">RUN</text>
<text x="510.5" y="144.1">+5V_B</text>
<text x="473.2" y="170.7">GPIO19_PWM3</text>
<text x="133.2" y="176.7">GPIO26_ADC0</text>
<text x="340.2" y="205.4">+3V3_SIG</text>
<text x="302.1" y="212.6">USB_D+</text>
<text x="302.1" y="220.2">USB_D-</text>
<text x="281.1" y="227.8">GPIO0_Ext1</text>
<text x="199.4" y="229.1">QSPI_SS</text>
<text x="199.4" y="232.9">QSPI_SD0</text>
<text x="278.5" y="232.9">GPIO2_LED_A2</text>
<text x="281.1" y="230.4">GPIO1_Ext2</text>
<text x="133.7" y="236">GPIO27_ADC1</text>
<text x="199.4" y="238">QSPI_SD2</text>
<text x="199.4" y="235.5">QSPI_SD1</text>
<text x="277.9" y="238">GPIO4_LED_In2</text>
<text x="278.5" y="235.5">GPIO3_LED_A1</text>
<text x="395.9" y="239.8">QSPI_SS</text>
<text x="473.3" y="235.6">GPIO18_Digital1</text>
<text x="199.4" y="244.3">QSPI_SCLK</text>
<text x="199.4" y="240.5">QSPI_SD3</text>
<text x="274.9" y="243.1">8 GPIO6_LED_TEST</text>
<text x="277.9" y="240.5">GPIO5_LED_In1</text>
<text x="286.2" y="245.6">GPIO7</text>
<text x="393.3" y="244.8">QSPI_SD0</text>
<text x="398.4" y="242.3">QSPI_SCLK</text>
<text x="275" y="250.7">GPIO9_GateInput2</text>
<text x="393.3" y="249.9">QSPI_SD2</text>
<text x="393.3" y="247.4">QSPI_SD1</text>
<text x="279.9" y="253.2">GPIO10_SWM</text>
<text x="393.3" y="252.5">QSPI_SD3</text>
<text x="199.4" y="263.4">XIN</text>
<text x="280.4" y="263.4">GPIO14_SWT</text>
<text x="199.4" y="268.5">XOUT</text>
<text x="285" y="265.9">GPIO15</text>
<text x="57.2" y="281.6">USB_D-</text>
<text x="199.4" y="281.2">RUN</text>
<text x="278.7" y="281.2">GPIO21_PWM1</text>
<text x="278.7" y="278.6">GPIO20_PWM2</text>
<text x="278.7" y="276.1">GPIO19_PWM3</text>
<text x="56.9" y="287.8">USB_D+</text>
<text x="279.1" y="286.3">GPIO23_SWTB</text>
<text x="199.4" y="292.6">SWCLK</text>
<text x="473.5" y="292.5">GPIO17_Digital2</text>
<text x="199.4" y="295.1">SWD</text>
<text x="279.2" y="299">GPIO27_ADC1</text>
<text x="279.2" y="296.4">GPIO26_ADC0</text>
<text x="279.2" y="304">GPIO29_ADC3</text>
<text x="279.2" y="301.5">GPIO28_ADC2</text>
<text x="438" y="305.8">XIN</text>
<text x="436.3" y="316">XOUT</text>
<text x="155.4" y="329.8">+3V3_SIG</text>
<text x="473.7" y="349.5">GPIO16_Digital3</text>
<text x="331.7" y="355.3">+3V3_SIG</text>
<text x="240.2" y="376.7">+5V_B</text>
</g>
<g font-size="1.8" fill="#a90000">
<text x="424" y="31.2">2</text>
<text x="432.9" y="31.2">1</text>
<text x="424.1" y="40.6">2</text>
<text x="433" y="40.6">1</text>
<text x="43.2" y="47.2">TN</text>
<text x="101.3" y="46.9" transform="rotate(-90 101.3 46.9)">3</text>
<text x="43.7" y="52.3">S</text>
<text x="43.9" y="49.8">T</text>
<text x="92.3" y="52">1</text>
<text x="510.7" y="53">2</text>
<text x="541.2" y="53">TN</text>
<text x="101.3" y="54.6" transform="rotate(-90 101.3 54.6)">2</text>
<text x="510.7" y="58">3</text>
<text x="523.4" y="55.5">1</text>
<text x="541.7" y="58">S</text>
<text x="541.8" y="55.5">T</text>
<text x="44.7" y="66.8">TN</text>
<text x="45.3" y="71.9">S</text>
<text x="45.4" y="69.3">T</text>
<text x="92.3" y="71.6">1</text>
<text x="101.3" y="66.5" transform="rotate(-90 101.3 66.5)">3</text>
<text x="101.3" y="74.1" transform="rotate(-90 101.3 74.1)">2</text>
<text x="142" y="93.7">1</text>
<text x="134.4" y="96.3">2</text>
<text x="142" y="98.8">3</text>
<text x="30.7" y="102.7">1</text>
<text x="30.7" y="105.3">2</text>
<text x="30.7" y="107.8">3</text>
<text x="56.1" y="102.7">4</text>
<text x="56.1" y="105.3">5</text>
<text x="56.1" y="107.8">6</text>
<text x="510.8" y="109">6</text>
<text x="523.5" y="111.5">7</text>
<text x="541.3" y="109">TN</text>
<text x="542" y="111.5">T</text>
<text x="510.8" y="114">5</text>
<text x="541.8" y="114">S</text>
<text x="38.5" y="135.1">1</text>
<text x="46.2" y="135.1">2</text>
<text x="45.6" y="165.2">TN</text>
<text x="46.3" y="167.8">T</text>
<text x="64.6" y="167.8">2</text>
<text x="68.2" y="165.6" transform="rotate(-90 68.2 165.6)">1</text>
<text x="511.1" y="165.6">2</text>
<text x="541.5" y="165.6">TN</text>
<text x="46.2" y="170.3">S</text>
<text x="68.2" y="171.9" transform="rotate(-90 68.2 171.9)">3</text>
<text x="76.8" y="171.6">2</text>
<text x="511.1" y="170.7">3</text>
<text x="523.8" y="168.1">1</text>
<text x="542.1" y="170.7">S</text>
<text x="542.2" y="168.1">T</text>
<text x="76.8" y="176.7">3</text>
<text x="89.5" y="174.1">1</text>
<text x="113.7" y="174.1">2</text>
<text x="113.7" y="179.2">3</text>
<text x="126.4" y="176.7">1</text>
<text x="224.5" y="212.9" transform="rotate(-90 224.5 212.9)">50</text>
<text x="227.1" y="212.9" transform="rotate(-90 227.1 212.9)">23</text>
<text x="232.2" y="212.9" transform="rotate(-90 232.2 212.9)">45</text>
<text x="236" y="212.9" transform="rotate(-90 236 212.9)">44</text>
<text x="241" y="212.9" transform="rotate(-90 241 212.9)">49</text>
<text x="243.6" y="212.9" transform="rotate(-90 243.6 212.9)">42</text>
<text x="246.1" y="212.9" transform="rotate(-90 246.1 212.9)">33</text>
<text x="248.7" y="212.9" transform="rotate(-90 248.7 212.9)">22</text>
<text x="251.2" y="212.9" transform="rotate(-90 251.2 212.9)">10</text>
<text x="253.7" y="212.3" transform="rotate(-90 253.7 212.3)">1</text>
<text x="257.6" y="212.9" transform="rotate(-90 257.6 212.9)">48</text>
<text x="261.4" y="212.9" transform="rotate(-90 261.4 212.9)">43</text>
<text x="274.3" y="220.2">46</text>
<text x="274.3" y="217.7">47</text>
<text x="46.1" y="224.5">TN</text>
<text x="46.8" y="227.1">T</text>
<text x="65.1" y="227.1">2</text>
<text x="68.7" y="224.9" transform="rotate(-90 68.7 224.9)">1</text>
<text x="274.9" y="227.8">2</text>
<text x="46.7" y="229.6">S</text>
<text x="68.7" y="231.2" transform="rotate(-90 68.7 231.2)">3</text>
<text x="77.3" y="230.9">6</text>
<text x="90" y="233.4">7</text>
<text x="114.2" y="233.4">6</text>
<text x="213.3" y="232.9">53</text>
<text x="213.3" y="229.1">56</text>
<text x="274.9" y="230.4">3</text>
<text x="274.9" y="232.9">4</text>
<text x="511.2" y="230.5">2</text>
<text x="523.9" y="233">1</text>
<text x="541.7" y="230.5">TN</text>
<text x="542.3" y="233">T</text>
<text x="77.3" y="236">5</text>
<text x="114.2" y="238.5">5</text>
<text x="126.9" y="236">7</text>
<text x="213.3" y="238">54</text>
<text x="213.3" y="235.5">55</text>
<text x="274.9" y="235.5">5</text>
<text x="274.9" y="238">6</text>
<text x="410.4" y="239.8">1</text>
<text x="419.7" y="236.9" transform="rotate(-90 419.7 236.9)">8</text>
<text x="511.2" y="235.6">3</text>
<text x="542.2" y="235.6">S</text>
<text x="213.3" y="240.5">51</text>
<text x="213.3" y="244.3">52</text>
<text x="274.9" y="240.5">7</text>
<text x="274.9" y="245.6">9</text>
<text x="274.9" y="243.1">8</text>
<text x="359.7" y="244.9">1</text>
<text x="367.3" y="244.9">2</text>
<text x="410.4" y="244.9">5</text>
<text x="410.4" y="242.3">6</text>
<text x="274.3" y="248.2">11</text>
<text x="274.3" y="250.7">12</text>
<text x="275" y="248.2">GPIO8_GateInput1</text>
<text x="410.4" y="247.4">2</text>
<text x="410.4" y="249.9">3</text>
<text x="274.3" y="253.2">13</text>
<text x="274.3" y="255.8">14</text>
<text x="410.4" y="252.5">7</text>
<text x="213.3" y="263.4">20</text>
<text x="274.3" y="263.4">17</text>
<text x="274.3" y="258.3">15</text>
<text x="274.3" y="260.9">16</text>
<text x="419.7" y="259.8" transform="rotate(-90 419.7 259.8)">4</text>
<text x="50.2" y="264.7">A4B9</text>
<text x="50.2" y="267.2">A9B4</text>
<text x="51.5" y="269.7">A5</text>
<text x="213.3" y="268.5">21</text>
<text x="274.3" y="265.9">18</text>
<text x="274.3" y="268.5">27</text>
<text x="51.4" y="272.3">B5</text>
<text x="274.3" y="271">28</text>
<text x="274.3" y="273.6">29</text>
<text x="51.4" y="279.9">B7</text>
<text x="51.5" y="277.4">A7</text>
<text x="213.3" y="281.2">26</text>
<text x="274.3" y="276.1">30</text>
<text x="274.3" y="278.6">31</text>
<text x="274.3" y="281.2">32</text>
<text x="51.4" y="285">B6</text>
<text x="51.5" y="282.4">A6</text>
<text x="274.3" y="286.3">35</text>
<text x="274.3" y="283.7">34</text>
<text x="511.4" y="287.4">6</text>
<text x="541.8" y="287.4">TN</text>
<text x="51.5" y="292.6">A8</text>
<text x="185.6" y="292.6">1</text>
<text x="213.3" y="292.6">24</text>
<text x="274.3" y="288.8">36</text>
<text x="274.3" y="291.3">37</text>
<text x="511.4" y="292.5">5</text>
<text x="524.1" y="289.9">7</text>
<text x="542.3" y="292.5">S</text>
<text x="542.5" y="289.9">T</text>
<text x="51.4" y="295.1">B8</text>
<text x="185.6" y="295.1">2</text>
<text x="185.6" y="297.7">3</text>
<text x="213.3" y="295.1">25</text>
<text x="274.3" y="296.4">38</text>
<text x="274.3" y="299">39</text>
<text x="32.1" y="301.8" transform="rotate(-90 32.1 301.8)">13</text>
<text x="39.8" y="303.6" transform="rotate(-90 39.8 303.6)">A12B1</text>
<text x="274.3" y="301.5">40</text>
<text x="274.3" y="304">41</text>
<text x="232.2" y="312" transform="rotate(-90 232.2 312)">19</text>
<text x="244.9" y="312" transform="rotate(-90 244.9 312)">57</text>
<text x="404.4" y="310.9">4</text>
<text x="409.3" y="308.7" transform="rotate(-90 409.3 308.7)">1</text>
<text x="413.3" y="310.9">2</text>
<text x="409.3" y="315" transform="rotate(-90 409.3 315)">3</text>
<text x="56.7" y="328.9">6</text>
<text x="69.4" y="328.9">1</text>
<text x="56.7" y="331.5">4</text>
<text x="69.4" y="331.5">2</text>
<text x="126.8" y="333">4</text>
<text x="126.8" y="330.5">6</text>
<text x="139.5" y="330.5">1</text>
<text x="139.5" y="333">2</text>
<text x="61" y="338.8" transform="rotate(-90 61 338.8)">7</text>
<text x="63.5" y="338.8" transform="rotate(-90 63.5 338.8)">3</text>
<text x="131.1" y="340.3" transform="rotate(-90 131.1 340.3)">7</text>
<text x="133.6" y="340.3" transform="rotate(-90 133.6 340.3)">3</text>
<text x="511.6" y="344.4">6</text>
<text x="524.3" y="347">7</text>
<text x="542.1" y="344.4">TN</text>
<text x="542.7" y="347">T</text>
<text x="511.6" y="349.5">5</text>
<text x="542.6" y="349.5">S</text>
<text x="331.5" y="369.4" transform="rotate(-90 331.5 369.4)">8</text>
<text x="362.7" y="369.3" transform="rotate(-90 362.7 369.3)">8</text>
<text x="392.7" y="371.2" transform="rotate(-90 392.7 371.2)">8</text>
<text x="419.7" y="369.6" transform="rotate(-90 419.7 369.6)">8</text>
<text x="446.4" y="369.9" transform="rotate(-90 446.4 369.9)">8</text>
<text x="45" y="382">1</text>
<text x="57.7" y="382">2</text>
<text x="331.5" y="380.8" transform="rotate(-90 331.5 380.8)">4</text>
<text x="362.7" y="380.7" transform="rotate(-90 362.7 380.7)">4</text>
<text x="392.7" y="382.6" transform="rotate(-90 392.7 382.6)">4</text>
<text x="419.7" y="381.1" transform="rotate(-90 419.7 381.1)">4</text>
<text x="446.4" y="381.3" transform="rotate(-90 446.4 381.3)">4</text>
<text x="45" y="384.6">3</text>
<text x="45" y="387.1">5</text>
<text x="45" y="389.6">7</text>
<text x="57.7" y="384.6">4</text>
<text x="57.7" y="387.1">6</text>
<text x="57.7" y="389.6">8</text>
<text x="45" y="392.2">9</text>
<text x="57.1" y="392.2">10</text>
</g>
<g font-size="1.3" fill="#0000c2">
<text x="485.3" y="22.2">https://modwiggler.com/forum/viewtopic.php?t=253062</text>
<text x="485.3" y="23.6">https://electronotes.netfirms.com/AN235.pdf</text>
</g>
<g font-size=".7" fill="#0000c2">
<text x="98.2" y="150.2">-50uA,</text>
<text x="101.6" y="150.2">250uW</text>
<text x="55" y="170.1">50uA</text>
</g>
</g></defs>
<g fill="none" stroke="#840000" stroke-width=".26">
<path d="M10 10h574v400h-574zM12 12h570v396h-570zM60 10v2M110 10v2M160 10v2M210 10v2M260 10v2M310 10v2M360 10v2M410 10v2M460 10v2M510 10v2"/>
<path d="M536.6 11.6h.7M560 10v2M10 60h2M582 60h2M10 110h2M582 110h2M10 160h2M582 160h2M10 210h2M582 210h2M10 260h2M582 260h2"/>
<path d="M10 310h2M582 310h2M10 360h2M474 376h108v32h-108zM582 360h2M474 397.5h108M474 391.5h108M479.5 396.2v.2M479.5 395.4v.2M481.7 393.5v.2M481.7 392.7v.2M484.6 392.1l-1.3 1.9"/>
<path d="M497.1 396.3h.6M497.1 395.4h.6M498.3 395.5l.6-.1 .1 1M498.3 394.9v1.5M60 408v2M110 408v2M160 408v2M210 408v2M260 408v2M310 408v2M360 408v2M410 408v2"/>
<path d="M460 408v2M474 404.5h108M474 401.5h108M494 401.5v3M494.7 406.6h.8M510 408v2M536.6 409.6h.7M558 401.5v6.5M560 408v2M567.3 406.6h.9M567.3 405.5l.4-.4v1.5"/>
</g>
<path d="M513.1 163.3l10.1 5.1-10.1 5.1z" fill="#ffffc2"/>
<g fill="none" stroke="#840000" stroke-width=".26">
<path d="M73.3 55.8h2.5M74.5 55.8l1.3 2.5h-2.5zM74.5 53.2v8.9h1.3l-1.3 1.3-1.2-1.3h1.2M91.7 50h5.1M96.8 51.3l2.5 1.3v2.5M96.8 47.5v5.1M99.3 45v2.5l-2.5 1.3M61.2 69.6h1.3M62.5 68.6h5.1v2h-5.1zM67.6 69.6h1.2M91.7 69.6h5.1M96.8 67.1v5"/>
<path d="M96.8 70.9l2.5 1.2v2.6M99.3 64.5v2.6l-2.5 1.2M510.5 165.9h2.6M510.5 170.9h2.6M513.1 163.3l10.1 5.1-10.1 5.1zM523.2 168.4h2.6"/>
<circle cx="96.8" cy="50" r="3.3"/>
<circle cx="96.8" cy="69.6" r="3.3"/>
</g>
<path d="M85.3 57.5l-.3 1.3M111.6 51.6h.9M66.7 67l.4 .4M67.1 66.6l-.5 .5M111.6 71.2h.9M513.6 166h1" fill="none" stroke="#006464" stroke-width=".26"/>
<g fill="#ffffc2" stroke="#ffffc2" stroke-width=".26">
<circle cx="96.8" cy="50" r="3.3"/>
<circle cx="96.8" cy="69.6" r="3.3"/>
</g>
<g fill="#840000" stroke="#840000" stroke-width=".26">
<path d="M98.3 51.3l.5 1-1 .3z"/>
<path d="M98.3 70.9l.5 1-1 .2z"/>
</g>
<path d="M41 222.3h5.1v8.8h-5.1z" fill="#ffffc2"/>
<path d="M39.8 224.8h1.2v2.5h-1.2z" fill="#840000" stroke="#840000" stroke-width=".26"/>
<path d="M530.4 168.4h1.2M531.6 167.4h5.1v2h-5.1zM536.7 168.4h1.3M541.5 170.9v1.3h1.3l-1.3 1.3-1.2-1.3h1.2M41 222.3h5.1v8.8h-5.1zM41.7 227.3l.6-.6 .6 .6v2.6h5.7M43.6 227.3l.6-.6 .6 .6h3.8M45.6 226.6l-.3 .5M46.1 224.8h-.8v2.3l-.2-.5" fill="none" stroke="#840000" stroke-width=".26"/>
<path d="M535 163.8h.8" fill="none" stroke="#006464" stroke-width=".26"/>
<path d="M544.1 163.3h5v8.9h-5z" fill="#ffffc2"/>
<path d="M549.1 165.9h1.3v2.5h-1.3z" fill="#840000" stroke="#840000" stroke-width=".26"/>
<g fill="none" stroke="#840000" stroke-width=".26">
<path d="M99.3 55.1v1.3h1.3l-1.3 1.3-1.3-1.3h1.3M442.6 78.1h1.3v-1.3l1.2 1.3-1.2 1.3v-1.3M442.6 96.4h1.3v-1.3l1.2 1.3-1.2 1.3v-1.3M442.6 87.2h1.3v-1.2l1.2 1.2-1.2 1.3v-1.3M426.1 129.9h1.3M427.4 128.9h5v2h-5zM432.4 129.9h8.9M436.2 128.7l2.6 1.2-2.6 1.3zM438.8 128.7v2.5M440.8 128.4v-.8h-.7h.7l-1.5 1.6M442.1 128.4v-.8h-.8h.8l-1.5 1.6M446.2 129.9h1.2v-1.2l1.3 1.2-1.3 1.3v-1.3"/>
<path d="M485.6 156v-1.3l-1.2 1.3 1.2 1.2v-1.2h2.6M488.2 154.9h5.1v2.1h-5.1zM493.3 156h1.2M499.4 156h1.2M500.6 154.9h5.1v2.1h-5.1zM505.7 156h1.3M509.5 145.7h2.1v5h-2.1zM510.5 144.4v1.3M510.5 150.7v1.3M514.5 156h1.2M515.7 154.9h5.1v2.1h-5.1zM520.8 156h1.3"/>
<path d="M113.2 179.5v1.2h1.2l-1.2 1.3-1.3-1.3h1.3M224.8 173.5l-.8 1.3M224.8 173.5v2.5M224.8 173.5l.8 1.3M487.9 170.9h1.3M489.2 169.9h5.1v2.1h-5.1zM494.3 170.9h1.3M499.4 175.8v4h1.2l-1.2 1.3-1.3-1.3h1.3M499.4 170.9v2.8M541.5 168.4h3.8l.7-.6 .6 .6M544.1 163.3h5v8.9h-5zM544.1 165.9h.7v2.2l.3-.5"/>
<path d="M544.6 167.6l.2 .5M548.5 168.4l-.6-.6-.7 .6v2.5h-5.7M204.5 188.7v1.3h1.2l-1.2 1.3-1.3-1.3h1.3M500.8 219.8h5v2.1h-5zM515.9 219.8h5.1v2.1h-5.1zM426.3 222.3v2.7M426.3 227.1v2.8M493.4 220.9v-1.3l-1.3 1.3 1.3 1.2v-1.2h1.3M499.5 220.9h1.3M505.8 220.9h1.3M514.6 220.9h1.3M521 220.9h1.2"/>
<path d="M530.5 233.3h1.2M531.7 232.3h5.1v2h-5.1zM536.8 233.3h1.3"/>
</g>
<path d="M226.4 172.5h.7M226.5 171.5l.2-.3v1.3M553.7 167.1h.7M433.7 227l.1 .2v.7" fill="none" stroke="#006464" stroke-width=".26"/>
<path d="M497.3 175.5h4.1M497.3 174h4.1M424.3 226.8h4.1M424.3 225.3h4.1" fill="none" stroke="#840000" stroke-width=".51"/>
<path d="M236.3 172.2l1.8-1.8 .8 .8-1.8 1.8z" fill="#ffffc2"/>
<path d="M236.5 172.3l.5 .5-1.3 .8z" fill="#840000" stroke="#840000" stroke-width=".26"/>
<path d="M204.5 178.6v2.8M215.9 178.6v2.8M235.7 173.6h.1M236.3 172.2l1.8-1.8 .8 .8-1.8 1.8zM204.5 183.4v2.8M215.9 183.4v2.8" fill="none" stroke="#840000" stroke-width=".26"/>
<path d="M202.4 183.1h4.1M202.4 181.6h4.1M213.9 183.1h4M213.9 181.6h4" fill="none" stroke="#840000" stroke-width=".51"/>
<path d="M211.8 183.3l.2 .2v.7M221.7 181.7h.7M223.2 183.3l.2 .2v.7" fill="none" stroke="#006464" stroke-width=".26"/>
<path d="M40.5 162.9h5.1v8.9h-5.1z" fill="#ffffc2"/>
<path d="M39.2 165.5h1.3v2.5h-1.3z" fill="#840000" stroke="#840000" stroke-width=".26"/>
<path d="M40.5 162.9h5.1v8.9h-5.1zM41.1 168l.7-.6 .6 .6v2.6h5.7M43.1 168l.6-.6 .6 .6h3.8M45.1 167.3l-.3 .5M45.6 165.5h-.8v2.3l-.2-.5M49.5 162.9l-.7 1.3M49.5 162.9v2.6M49.5 162.9l.8 1.3" fill="none" stroke="#840000" stroke-width=".26"/>
<path d="M51.3 160.7l-.4 1.2" fill="none" stroke="#006464" stroke-width=".26"/>
<path d="M78.7 169.3l10.2 5.1-10.2 5.1z" fill="#ffffc2"/>
<g fill="none" stroke="#840000" stroke-width=".26">
<path d="M442.6 105.5h1.3v-1.2l1.2 1.2-1.2 1.3v-1.3M48.1 170.6v1.2h1.3l-1.3 1.3-1.2-1.3h1.2M50.8 168h1.3M52.1 167h5v2h-5zM57.1 168h1.3M65.9 168h1M67.4 165.5h2.1v5.1h-2.1zM68.5 164.2v1.3M76.2 171.8h2.5M78.7 169.3l10.2 5.1-10.2 5.1zM78.7 176.9h-2.5v1.3h1.3l-1.3 1.3-1.3-1.3h1.3M79.9 161h1.3"/>
<path d="M81.2 160h5v2.1h-5zM86.2 161h1.3M88.9 174.4h2.5"/>
</g>
<path d="M85.4 158.4l.4 .5M85.8 158l-.5 .5M90.2 146.5l.5 1.3 .4-1.3M56.3 165.4l.4 .5M56.7 165l-.5 .5M74.4 169.3l.4 .5M74.8 169l-.5 .4M79.3 171.9h.9" fill="none" stroke="#006464" stroke-width=".26"/>
<g fill="#840000" stroke="#840000" stroke-width=".26">
<path d="M91.9 147.2l1.3-.8v.8h1.3h-1.3v.8z"/>
<path d="M66.2 167.5l1.1 .5-1.1 .5z"/>
</g>
<path d="M115.7 171.8l10.2 5.1-10.2 5.1z" fill="#ffffc2"/>
<g fill="none" stroke="#840000" stroke-width=".26">
<path d="M59.3 108.1v1.2h1.3l-1.3 1.3-1.3-1.3h1.3M41.3 135.4h-3.3v1.3h1.2l-1.2 1.2-1.3-1.2h1.3M41.3 134.1h3.5M42 132.6h2.1M43.1 132.6v1.5M44.8 135.4h3.3M113.2 174.4h2.5M113.2 179.5h2.5M115.7 171.8l10.2 5.1-10.2 5.1zM125.9 176.9h2.5"/>
<circle cx="41.5" cy="135.4" r=".25"/>
<circle cx="44.6" cy="135.4" r=".25"/>
</g>
<path d="M47.6 130a.81 .81 0 0 1 .6 .7 .81 .81 0 0 1-.6 .8M48.8 130.8l.7-.1 .1-.6-.8-.1v1.5M116.2 174.5h1M125.9 170.3l.4-.9v1.3M127.6 169.5h-.7a.53 .53 0 0 0 .6 .7v.4h-.6" fill="none" stroke="#006464" stroke-width=".26"/>
<path d="M33.9 100.5h20.3v10.1h-20.3z" fill="#ffffc2"/>
<path d="M27.1 108.1v1.2h1.2l-1.2 1.3-1.3-1.3h1.3M28.8 103h5.1M28.8 105.5h5.1M28.8 108.1h5.1M33.9 100.5h20.3v10.1h-20.3zM54.2 103h5.1M54.2 105.5h5.1M54.2 108.1h5.1" fill="none" stroke="#840000" stroke-width=".26"/>
<path d="M38.1 45h5.1v8.8h-5.1z" fill="#ffffc2"/>
<path d="M36.8 47.5h1.3v2.5h-1.3z" fill="#840000" stroke="#840000" stroke-width=".26"/>
<path d="M38.1 45h5.1v8.8h-5.1zM38.7 50l.7-.6 .6 .6v2.6h5.7M40.6 50l.7-.6 .6 .6h3.8M42.7 49.3l-.3 .5M43.2 47.5h-.8v2.3l-.2-.5" fill="none" stroke="#840000" stroke-width=".26"/>
<path d="M39.6 64.5h5.1v8.9h-5.1z" fill="#ffffc2"/>
<path d="M38.4 67.1h1.2v2.5h-1.2z" fill="#840000" stroke="#840000" stroke-width=".26"/>
<g fill="none" stroke="#840000" stroke-width=".26">
<path d="M45.7 52.6v1.2h1.3l-1.3 1.3-1.3-1.3h1.3M499 43.3h1.3M500.3 42.3h5v2h-5zM505.3 43.3h1.3M514.1 43.3h1.3M515.4 42.3h5v2h-5zM520.4 43.3h1.3M530 55.8h1.2M531.2 54.7h5.1v2.1h-5.1zM536.3 55.8h1.3M39.6 64.5h5.1v8.9h-5.1zM40.3 69.6l.6-.6 .6 .6v2.5h5.7v1.3h1.3l-1.3 1.3-1.2-1.3h1.2"/>
<path d="M42.2 69.6l.6-.6 .6 .6h3.8M44.2 68.8l-.3 .5M44.7 67.1h-.8v2.2l-.2-.5M73 74.9h2.6M74.3 72.4v8.9h1.3l-1.3 1.3-1.3-1.3h1.3M74.3 74.9l1.3 2.6h-2.6zM99.3 74.7v1.2h1.3l-1.3 1.3-1.3-1.3h1.3M224.8 379.3v1.3M223.8 380.6h2v5.1h-2zM224.8 385.7v1.3"/>
</g>
<path d="M85.1 76.7l-.3 1.3" fill="none" stroke="#006464" stroke-width=".26"/>
<path d="M543.7 50.7h5.1v8.9h-5.1z" fill="#ffffc2"/>
<path d="M548.8 53.2h1.2v2.6h-1.2z" fill="#840000" stroke="#840000" stroke-width=".26"/>
<path d="M509.1 33h2.1v5.1h-2.1zM510.2 31.8v1.2M510.2 38.1v1.3M541.1 55.8h3.9l.6-.7 .6 .7M543.7 50.7h5.1v8.9h-5.1zM543.7 53.2h.7v2.3l.3-.5M544.2 55l.2 .5M548.1 55.8l-.6-.7-.6 .7v2.5h-5.8v1.3h1.3l-1.3 1.2-1.2-1.2h1.2" fill="none" stroke="#840000" stroke-width=".26"/>
<path d="M512.7 50.7l10.2 5.1-10.2 5z" fill="#ffffc2"/>
<path d="M510.2 53.2h2.5M510.2 58.3h2.5M512.7 50.7l10.2 5.1-10.2 5zM522.9 55.8h2.5" fill="none" stroke="#840000" stroke-width=".26"/>
<path d="M513.2 53.3h1" fill="none" stroke="#006464" stroke-width=".26"/>
<path d="M515.5 69l1.8-1.8 .7 .7-1.7 1.8z" fill="#ffffc2"/>
<path d="M515.6 69.1l.5 .5-1.2 .8z" fill="#840000" stroke="#840000" stroke-width=".26"/>
<path d="M510.2 29.2l-.8 1.3M510.2 29.2v2.6M510.2 29.2l.7 1.3M486.5 43.3h1.3M487.8 42.3h5.1v2h-5.1zM492.9 43.3h1.3M514.9 70.4h.1M515.5 69l1.8-1.8 .7 .7-1.7 1.8z" fill="none" stroke="#840000" stroke-width=".26"/>
<path d="M512 26.9l-.4 1.3" fill="none" stroke="#006464" stroke-width=".26"/>
<path d="M426.7 39.6h5.1v2.6h-5.1z" fill="#ffffc2"/>
<path d="M426.7 39.6h5.1v2.6h-5.1zM422.9 40.9h3.8M426.7 40.8h1.3v.2h-1.3zM430.5 40.8h1.3v.2h-1.3zM431.8 40.9h3.8" fill="none" stroke="#840000" stroke-width=".26"/>
<path d="M434.1 38.5h.7M434.1 37.6l.3-.4v1.3" fill="none" stroke="#006464" stroke-width=".26"/>
<path d="M426.6 30.2h5.1v2.6h-5.1z" fill="#ffffc2"/>
<path d="M422.8 31.5h3.8M426.6 30.2h5.1v2.6h-5.1zM426.6 31.4h1.3v.2h-1.3zM430.4 31.4h1.3v.2h-1.3zM431.7 31.5h3.8M485.3 43.3v-1.3l-1.3 1.3 1.3 1.3v-1.3h1.2M223.8 389.1h2v5.1h-2zM224.8 387.9v1.2M224.8 394.2v1.3M236.3 384.3v2.8M236.3 389.1v2.8" fill="none" stroke="#840000" stroke-width=".26"/>
<path d="M433.9 29.1h.8M433.9 28.2l.4-.4v1.3" fill="none" stroke="#006464" stroke-width=".26"/>
<path d="M234.3 388.9h4.1M234.3 387.4h4.1" fill="none" stroke="#840000" stroke-width=".51"/>
<path d="M230.4 363.3l1.8-1.7 .7 .7-1.8 1.8z" fill="#ffffc2"/>
<g fill="#840000" stroke="#840000" stroke-width=".26">
<path d="M230.5 363.5l.5 .5-1.3 .7z"/>
<path d="M66.7 226.8l1.1 .5-1.1 .5z"/>
<path d="M92.5 206.5l1.2-.8v.8h1.3h-1.3v.8z"/>
</g>
<path d="M81.7 219.3h5v2.1h-5zM66.4 227.3h1M67.9 224.8h2.1v5.1h-2.1zM69 223.5v1.3M76.7 236.2v1.3h1.3l-1.3 1.3-1.3-1.3h1.3M80.4 220.3h1.3M86.7 220.3h1.3M229.7 364.7h.1M230.4 363.3l1.8-1.7 .7 .7-1.8 1.8zM214.2 395.4v1.2h1.3l-1.3 1.3-1.2-1.3h1.2" fill="none" stroke="#840000" stroke-width=".26"/>
<path d="M85.9 217.7l.4 .5M86.3 217.3l-.5 .5M90.7 205.8l.5 1.3 .4-1.3M74.9 228.6l.4 .5M75.3 228.3l-.5 .5M245 364.9h.5M245 364.2l.4-.1 .2 .3-.6 .1" fill="none" stroke="#006464" stroke-width=".26"/>
<path d="M79.2 228.6l10.2 5.1-10.2 5.1z" fill="#ffffc2"/>
<path d="M76.7 236.2h2.5M76.7 231.1h2.5M79.2 228.6l10.2 5.1-10.2 5.1zM89.4 233.7h2.5M100.8 233.7h1.3M102.1 232.7h5.1v2h-5.1zM107.2 233.7h1.3M113.7 238.8v1.2h1.2l-1.2 1.3-1.3-1.3h1.3" fill="none" stroke="#840000" stroke-width=".26"/>
<path d="M79.8 231.2h.9M106.4 231l.3 .5M106.7 230.7l-.4 .5" fill="none" stroke="#006464" stroke-width=".26"/>
<path d="M116.2 231.1l10.2 5.1-10.2 5.1z" fill="#ffffc2"/>
<g fill="none" stroke="#840000" stroke-width=".26">
<path d="M421.9 42.2h2v5h-2zM422.1 49.8l.8 1.3M422.9 40.9v1.3M422.9 47.2v3.9M423.7 49.8l-.8 1.3M434.6 42.2h2v5h-2zM434.8 49.8l.8 1.3M435.6 40.9v1.3M435.6 47.2v3.9M436.4 49.8l-.8 1.3M422.5 78.1h1.3M423.8 77.1h5.1v2h-5.1z"/>
<path d="M428.9 78.1h8.9M432.7 76.8l2.5 1.3-2.5 1.3zM435.2 76.8v2.6M437.3 76.6v-.8h-.8h.8l-1.6 1.5M438.5 76.6v-.8h-.7h.7l-1.5 1.5M422.5 96.4h1.3M422.5 87.2h1.3M423.8 95.4h5.1v2h-5.1zM423.8 86.2h5.1v2.1h-5.1zM428.9 96.4h8.9M428.9 87.2h8.9M432.7 95.1l2.5 1.3-2.5 1.3z"/>
<path d="M432.7 86l2.5 1.2-2.5 1.3zM435.2 86v2.5M435.2 95.1v2.6M437.3 94.9v-.8h-.8h.8l-1.6 1.5M437.3 85.7v-.7h-.8h.8l-1.6 1.5M438.5 94.9v-.8h-.7h.7l-1.5 1.5M438.5 85.7v-.7h-.7h.7l-1.5 1.5M485.4 99.3v-1.3l-1.3 1.3 1.3 1.3v-1.3h2.5M487.9 98.3h5.1v2h-5.1zM493 99.3h1.3M499.1 99.3h1.3M500.4 98.3h5.1v2h-5.1z"/>
<path d="M505.5 99.3h1.2M509.3 89h2v5.1h-2zM510.3 85.2l-.8 1.3M510.3 85.2v3.8M510.3 94.1v1.3M510.3 85.2l.7 1.3M514.2 99.3h1.3M515.5 98.3h5.1v2h-5.1zM520.6 99.3h1.2M422.5 105.5h1.3M423.8 104.5h5.1v2.1h-5.1zM428.9 105.5h8.9"/>
<path d="M432.7 104.3l2.5 1.2-2.5 1.3zM435.2 104.3v2.5M437.3 104v-.7h-.8h.8l-1.6 1.5M438.5 104v-.7h-.7h.7l-1.5 1.5M487.7 114.3h1.2M488.9 113.3h5.1v2h-5.1zM494 114.3h1.3M499.1 119.1v4.1h1.3l-1.3 1.3-1.3-1.3h1.3M499.1 114.3v2.8M530.1 111.8h1.3M531.4 110.7h5v2.1h-5zM536.4 111.8h1.3"/>
<path d="M541.3 114.3v1.3h1.2l-1.2 1.2-1.3-1.2h1.3M115.8 163.4h1.3M117.1 162.4h5.1v2.1h-5.1zM122.2 163.4h1.2M100.2 206.5h1.3M101.5 205.5h5.1v2h-5.1zM106.6 206.5h1.2M116.8 211.8h2.8M121.7 211.8h2.8M113.7 238.8h2.5M113.7 233.7h2.5M116.2 231.1l10.2 5.1-10.2 5.1z"/>
<path d="M116.3 222.8h1.3M117.6 221.7h5.1v2.1h-5.1zM122.7 222.8h1.3M126.4 236.2h2.5"/>
</g>
<g fill="none" stroke="#006464" stroke-width=".26">
<path d="M420.1 44.1h.7M424.4 52h.8l-.4 .4M425 52.4l.2 .3-.2 .5M437.1 52h.8l-.4 .4M437.7 52.4l.2 .3-.2 .5M436.4 72.4h.7M512.1 82.9l-.4 1.3M514.9 90.9h.7M105.7 203.9l.4 .4M106.1 203.5l-.5 .5M116.7 233.8h1M126.4 229.6l.4-.9v1.3"/>
<path d="M128.1 228.8l-.7 .1a.53 .53 0 0 0 .6 .6v.4h-.6"/>
</g>
<path d="M497.1 118.9h4M497.1 117.3h4M119.9 209.8v4.1M121.4 209.8v4.1" fill="none" stroke="#840000" stroke-width=".51"/>
<path d="M543.8 106.7h5.1v8.9h-5.1z" fill="#ffffc2"/>
<path d="M548.9 109.2h1.3v2.6h-1.3z" fill="#840000" stroke="#840000" stroke-width=".26"/>
<path d="M541.3 111.8h3.8l.6-.7 .7 .7M543.8 106.7h5.1v8.9h-5.1zM543.8 109.2h.8v2.3l.2-.5M544.3 111l.3 .5M548.3 111.8l-.7-.7-.6 .7v2.5h-5.7" fill="none" stroke="#840000" stroke-width=".26"/>
<path d="M512.8 106.7l10.2 5.1-10.2 5z" fill="#ffffc2"/>
<g fill="none" stroke="#840000" stroke-width=".26">
<path d="M487.6 58.3h1.2M488.8 57.3h5.1v2h-5.1zM493.9 58.3h1.3M499 58.3v2.8M499 63.1v4.1h1.3l-1.3 1.3-1.3-1.3h1.3M510.3 114.3h2.5M510.3 109.2h2.5M512.8 106.7l10.2 5.1-10.2 5zM523 111.8h2.5M146.6 386v2.5M146.6 387.2h2.5M146.6 384.7v5.1"/>
<path d="M147.3 386.5h-1.5l-.3 .2"/>
</g>
<path d="M492.2 53.7h.8M513.4 109.3h.9M135.2 389h.8M143.6 387.7h.8l-.4 .5 .4 .1v.5l-.2 .2h-.4" fill="none" stroke="#006464" stroke-width=".26"/>
<path d="M497 62.9h4M497 61.3h4" fill="none" stroke="#840000" stroke-width=".51"/>
<path d="M146.6 386.5l.7 1.5h-1.5z" fill="#840000" stroke="#840000" stroke-width=".26"/>
<path d="M500.6 356.7l1.8-1.7 .8 .7-1.8 1.8z" fill="#ffffc2"/>
<path d="M500.8 356.9l.5 .5-1.3 .7z" fill="#840000" stroke="#840000" stroke-width=".26"/>
<path d="M499.9 334.8h1.2M501.1 333.8h5.1v2h-5.1zM506.2 334.8h1.3M500 358.1h.1M500.6 356.7l1.8-1.7 .8 .7-1.8 1.8zM542 349.8v1.2h1.3l-1.3 1.3-1.2-1.3h1.2" fill="none" stroke="#840000" stroke-width=".26"/>
<path d="M509.7 357.1v1.1l.2 .1" fill="none" stroke="#006464" stroke-width=".26"/>
<path d="M544.6 342.1h5.1v8.9h-5.1z" fill="#ffffc2"/>
<path d="M549.7 344.7h1.2v2.5h-1.2z" fill="#840000" stroke="#840000" stroke-width=".26"/>
<g fill="none" stroke="#840000" stroke-width=".26">
<path d="M112.8 339.6v1.3h1.2l-1.2 1.2-1.3-1.2h1.3M112.8 331.3v2.8M112.8 336.2v2.8M493.8 334.8v-1.3l-1.3 1.3 1.3 1.2v-1.2h1.2M515 334.8h1.3M516.3 333.8h5v2h-5zM521.3 334.8h1.3M542 347.2h3.8l.7-.6 .6 .6M544.6 342.1h5.1v8.9h-5.1zM544.6 344.7h.7v2.3l.3-.5M545.1 346.5l.2 .5M549 347.2l-.6-.6-.6 .6v2.6h-5.8"/>
<path d="M102.7 379.7v2.8M113 379.7v2.8M126.6 376.4l1.3 .8M126.6 376.4h2.6M127.9 375.7l-1.3 .7M133 376.4h1.2M134.2 375.4h5.1v2h-5.1zM139.3 376.4h1.3M157.1 378.8v1.3M102.7 384.6v5.5M102.7 392.2v2.8M113 384.6v5.5"/>
<path d="M113 392.2v2.8M113.5 387.4h1.3v-1.3l1.3 1.3-1.3 1.2v-1.2M146.6 394.8v1.3h1.2l-1.2 1.3-1.3-1.3h1.3M156.1 388.6h2v5.1h-2zM156.1 380.1h2v5.1h-2zM157.1 385.2v1.3M157.1 387.4v1.2M157.1 393.7v1.3"/>
</g>
<path d="M110.7 335.9h4.1M110.7 334.4h4.1M100.7 384.3h4.1M100.7 382.8h4.1M100.7 391.9h4.1M100.7 390.4h4.1M111 384.3h4.1M111 382.8h4.1M111 391.9h4.1M111 390.4h4.1" fill="none" stroke="#840000" stroke-width=".51"/>
<path d="M125.8 375.7l-.5 1.3M134.3 374.2l-.1 .3M142.5 373l-.3 1.3M110.1 384.5l.2 .2v.6M110.1 392.1l.2 .2v.7M118.8 382.9h.7M120.4 384.5l.1 .2v.6M120.4 392.1l.1 .2v.7" fill="none" stroke="#006464" stroke-width=".26"/>
<path d="M150.4 321.4l1.7-1.7 .8 .7-1.8 1.8z" fill="#ffffc2"/>
<path d="M150.5 321.6l.5 .5-1.3 .7z" fill="#840000" stroke="#840000" stroke-width=".26"/>
<path d="M112.8 327.5l-.8 1.3M112.8 327.5v2.6M112.8 327.5l.7 1.3M149.7 322.8h.1M150.4 321.4l1.7-1.7 .8 .7-1.8 1.8zM153.5 339.7v1.3h1.3l-1.3 1.3-1.2-1.3h1.2M132.6 343.8v1.3h1.3l-1.3 1.2-1.3-1.2h1.3" fill="none" stroke="#840000" stroke-width=".26"/>
<path d="M115.2 325.2l-.4 1.3M159.3 322.2l.4 .1M159.7 322.2v1l-.2 .3M159.7 323h-.4" fill="none" stroke="#006464" stroke-width=".26"/>
<path d="M128.8 328.2h10.1v10.1h-10.1z" fill="#ffffc2"/>
<g fill="none" stroke="#840000" stroke-width=".26">
<path d="M541.7 235.8v1.3h1.2l-1.2 1.3-1.3-1.3h1.3M405.8 311.2h.2M407.3 308.6h-1.3v5.1h1.3M409.6 307.3v1.3M409.6 313.2v.5M411.9 308.6h1.2v5.1h-1.2M414.7 311.2h1.2v-1.3l1.3 1.3-1.3 1.2v-1.2M423.5 316.2h1.3M424.8 315.2h5.1v2h-5.1zM429.9 316.2h1.3M126.2 330.7h2.6M126.2 333.2h2.6"/>
<path d="M128.8 328.2h10.1v10.1h-10.1zM131.3 338.3v2.6M133.9 338.3v2.6M138.9 330.7h2.6M138.9 333.2h2.6M91.4 377.2v5.3M91.4 377.2l-.7 1.3M91.4 377.2l.8 1.3M67.9 392.4h2.6M72.1 389.7l1.8 1.1-2.6 4.4-1.8-1.1zM73 392.4h2.6M75.7 382.3h7.6"/>
<path d="M78.2 381l2.6 1.3-2.6 1.2zM80.1 381.6v-.6h.7v2.5h.6v-.6M91.4 384.6v5.5M91.4 392.2v2.8"/>
</g>
<g fill="none" stroke="#006464" stroke-width=".26">
<path d="M432.8 306.7l.3 .2 .1 .3-.5 .2M432.8 306.1l.4 .1M433.8 306.1v1.3M140.2 326.4l.4 .6M140.4 325.8l.2 .2-.2 .4M82.7 378.6h.3l.3 .2-.1 .8-.5 .3M83.3 379.1l-.3 .3-.3-.1M93.9 374.9l-.5 1.3M69.2 399.2v1.3M69.2 399.7h-.3l-.3 .2 .2 .5h.4M84 399.8h.4M84.6 399.2h-.6v1.3"/>
<path d="M93 398.4l.4 1.3 .5-1.3"/>
</g>
<path d="M91.4 395v1.2h.8l-.8 1.3-.7-1.3h.7z" fill="#840000" stroke="#840000" stroke-width=".26"/>
<path d="M408.3 309.1h2.5M408.3 313.2h2.5M89.4 391.9h4.1M89.4 390.4h4.1M89.4 384.3h4.1M89.4 382.8h4.1" fill="none" stroke="#840000" stroke-width=".51"/>
<path d="M407 310h5.1v2.3h-5.1z" fill="none" stroke="#840000" stroke-width=".3"/>
<path d="M412.4 237.5h15.2v20.3h-15.2z" fill="#ffffc2"/>
<g fill="none" stroke="#840000" stroke-width=".26">
<path d="M412.4 237.5h15.2v20.3h-15.2zM420 235v2.5M409.8 240h2.6M409.8 247.7h2.6M409.8 250.2h2.6M409.8 245.1h2.6M409.8 242.6h2.6M409.8 252.7h2.6M420 257.8v2.6M541.8 292.7v1.3h1.3l-1.3 1.3-1.3-1.3h1.3M388 318.8v1.2h1.3l-1.3 1.3-1.3-1.3h1.3M390.5 316.2h2.8"/>
<path d="M395.4 316.2h2.7M403.2 311.2v-1.3l-1.2 1.3 1.2 1.2v-1.2h1.3"/>
</g>
<path d="M425.1 236.5h.7M433.7 237.6l.4 .1M433.9 238.3l.2 .2-.2 .4M419.1 244.3a1.49 1.49 0 0 1 0 1.8M420.1 247.3v.9" fill="none" stroke="#006464" stroke-width=".26"/>
<path d="M393.6 314.2v4.1M395.1 314.2v4.1" fill="none" stroke="#840000" stroke-width=".51"/>
<path d="M513.3 285.1l10.2 5.1-10.2 5.1z" fill="#ffffc2"/>
<path d="M514.7 277.7h1.3M516 276.7h5.1v2.1h-5.1zM521.1 277.7h1.3M510.8 292.7h2.5M510.8 287.7h2.5M513.3 285.1l10.2 5.1-10.2 5.1zM523.5 290.2h2.5" fill="none" stroke="#840000" stroke-width=".26"/>
<path d="M513.9 287.8h.9" fill="none" stroke="#006464" stroke-width=".26"/>
<path d="M544.3 285.1h5.1v8.9h-5.1z" fill="#ffffc2"/>
<path d="M549.4 287.7h1.3v2.5h-1.3z" fill="#840000" stroke="#840000" stroke-width=".26"/>
<path d="M530.6 290.2h1.3M531.9 289.2h5.1v2h-5.1zM537 290.2h1.2M541.8 290.2h3.8l.6-.6 .7 .6M544.3 285.1h5.1v8.9h-5.1zM544.3 287.7h.8v2.2l.2-.5M544.8 289.4l.3 .5M548.8 290.2l-.7-.6-.6 .6v2.5h-5.7" fill="none" stroke="#840000" stroke-width=".26"/>
<path d="M544.2 228.2h5.1v8.9h-5.1z" fill="#ffffc2"/>
<path d="M549.3 230.8h1.2v2.5h-1.2z" fill="#840000" stroke="#840000" stroke-width=".26"/>
<path d="M541.7 233.3h3.8l.6-.6 .6 .6M544.2 228.2h5.1v8.9h-5.1zM544.2 230.8h.8v2.2l.2-.5M544.7 232.5l.3 .5M548.6 233.3l-.6-.6-.6 .6v2.5h-5.7" fill="none" stroke="#840000" stroke-width=".26"/>
<path d="M513.2 228.2l10.2 5.1-10.2 5.1z" fill="#ffffc2"/>
<g fill="none" stroke="#840000" stroke-width=".26">
<path d="M510.7 230.8h2.5M510.7 235.8h2.5M513.2 228.2l10.2 5.1-10.2 5.1zM523.4 233.3h2.5M493.5 277.7v-1.2l-1.2 1.2 1.2 1.3v-1.3h1.3M499.6 277.7h1.3M500.9 276.7h5.1v2.1h-5.1zM506 277.7h1.2M433.1 363.9v1.2h1.2l-1.2 1.3-1.3-1.3h1.3M446.7 360.6v2.5M446.7 367.3v3.8M446.7 378.7v3.8"/>
<path d="M446.7 360.6l-.8 1.2M446.7 360.6l.7 1.2M452.1 364.1h2.8M456.9 364.1h2.8v1.3h1.3l-1.3 1.2-1.2-1.2h1.2M75.6 392.4h7.6M77.5 391.8v-.6h.6v2.5h.6v-.6M78.1 392.4l2.5-1.2v2.5zM433.1 382.3v1.2h1.2l-1.2 1.3-1.3-1.3h1.3M452.1 382.5h2.8M456.9 382.5h2.8v1.3h1.3l-1.3 1.3-1.2-1.3h1.2"/>
</g>
<path d="M513.7 230.9h1M449.1 358.3l-.4 1.2M456.8 358.4h.7M457.8 360l.2 .1v.7M457.8 378.4l.2 .2v.6M81.9 388.8l.4-.1 .2 .3-.1 .7-.5 .3M82.5 389.3l-.2 .2h-.4M448.2 388.1l.5 1.3 .4-1.3" fill="none" stroke="#006464" stroke-width=".26"/>
<path d="M455.2 362.1v4M456.7 362.1v4M455.2 380.5v4.1M456.7 380.5v4.1" fill="none" stroke="#840000" stroke-width=".51"/>
<path d="M446.7 384.7v1.3h.7l-.7 1.2-.8-1.2h.8z" fill="#840000" stroke="#840000" stroke-width=".26"/>
<path d="M513.6 342.1l10.1 5.1-10.1 5.1z" fill="#ffffc2"/>
<g fill="none" stroke="#840000" stroke-width=".26">
<path d="M365.6 77.9h1.3M366.9 76.8h5.1v2.1h-5.1zM372 77.9h8.9M375.8 76.6l2.5 1.3-2.5 1.2zM378.3 76.6v2.5M380.4 76.3v-.7h-.8h.8l-1.6 1.5M381.6 76.3v-.7h-.7h.7l-1.5 1.5M385.7 77.9h1.3v-1.3l1.2 1.3-1.2 1.2v-1.2M132.6 96.5v-1.2l-1.3 1.2 1.3 1.3v-1.3h1.3M365.6 87h1.3M366.9 86h5.1v2h-5.1zM372 87h8.9"/>
<path d="M375.8 85.7l2.5 1.3-2.5 1.3zM378.3 85.7v2.6M380.4 85.5v-.8h-.8h.8l-1.6 1.5M381.6 85.5v-.8h-.7h.7l-1.5 1.5M385.7 87h1.3v-1.3l1.2 1.3-1.2 1.3v-1.3M100.3 174.4h1.3M101.6 173.4h5.1v2h-5.1zM106.7 174.4h1.2M261.6 173.5l-.7 1.3M261.6 173.5v2.5M261.6 173.5l.8 1.3M270.5 178.6v2.8"/>
<path d="M281.9 178.6v2.8M293.4 178.6v2.8M304.8 178.6v2.8M316.2 178.6v2.8M327.7 178.6v2.8M339.1 178.6v2.8M270.5 183.4v2.8M270.5 193.8v2.8M270.5 198.6v2.8M281.9 183.4v2.8M293.4 183.4v2.8M304.8 183.4v2.8"/>
<path d="M316.2 183.4v2.8M327.7 183.4v2.8M339.1 190v1.3h1.3l-1.3 1.2-1.3-1.2h1.3M339.1 183.4v2.8M356.5 199.3v2.8M270.5 202.7v1.3h1.3l-1.3 1.2-1.3-1.2h1.3M288.3 212.9h1.3M289.6 219.5h5v2h-5zM289.6 211.8h5v2.1h-5zM294.6 212.9h1.3M356.5 210.7v1.3h1.3l-1.3 1.2-1.3-1.2h1.3M356.5 204.1v2.8"/>
<path d="M420 217.2l-.8 1.2M420 217.2v2.5M420 217.2l.8 1.2M288.3 220.5h1.3M294.6 220.5h1.3M403.7 227.3h2.1v5.1h-2.1zM404.7 226.1v1.2M404.7 232.4v1.3M511 349.8h2.6M511 344.7h2.6M513.6 342.1l10.1 5.1-10.1 5.1zM523.7 347.2h2.6"/>
<path d="M530.9 347.2h1.2M532.1 346.2h5.1v2h-5.1zM537.2 347.2h1.3"/>
</g>
<g fill="none" stroke="#006464" stroke-width=".26">
<path d="M105 169.8h.7M105.9 171.7l.3 .5M106.2 171.4l-.5 .5M263.1 171.2h.8l-.4 .5M263.7 171.7l.2 .2-.2 .6M277.8 183.3l.2 .2v.7M289.3 183.3l.1 .2v.7M300.7 183.3l.2 .2v.7M312.1 183.3l.2 .2v.7M323.6 183.3l.1 .2v.7M333.4 181.7h.7M335 183.3l.2 .2v.7"/>
<path d="M346.4 183.3l.2 .2v.7M293 208.3h.7M363.8 204l.2 .2v.7M421.5 214.9h.8l-.4 .5M422 215.4l.3 .2-.3 .6M514.1 344.8h1"/>
</g>
<g fill="none" stroke="#840000" stroke-width=".51">
<path d="M268.5 183.1h4M268.5 181.6h4M268.5 198.4h4M268.5 196.9h4M279.9 183.1h4.1M279.9 181.6h4.1M291.3 183.1h4.1M291.3 181.6h4.1M302.8 183.1h4M302.8 181.6h4M314.2 183.1h4.1M314.2 181.6h4.1"/>
<path d="M325.6 183.1h4.1M325.6 181.6h4.1M337.1 183.1h4M337.1 181.6h4M354.5 203.8h4M354.5 202.3h4"/>
</g>
<path d="M135.8 92.7h6.3v7.6h-6.3z" fill="#ffffc2"/>
<g fill="none" stroke="#840000" stroke-width=".26">
<path d="M133.9 96.5h2.5M135.8 92.7h6.3v7.6h-6.3zM140.6 94.2l-3.3 2.1M141.5 94h2.5M141.5 99.1h2.5"/>
<circle cx="136.9" cy="96.5" r=".46"/>
<circle cx="141" cy="99.1" r=".46"/>
<circle cx="141" cy="94" r=".46"/>
</g>
<path d="M136.3 166.8l1.7-1.8 .8 .7-1.8 1.8z" fill="#ffffc2"/>
<path d="M136.4 166.9l.5 .5-1.3 .7z" fill="#840000" stroke="#840000" stroke-width=".26"/>
<path d="M99.7 147.2h1.3M101 146.2h5v2h-5zM106 147.2h1.3M116.3 152.5h2.8M121.2 152.5h2.8M135.6 168.1h.1M136.3 166.8l1.7-1.8 .8 .7-1.8 1.8zM62.5 342.3v1.2h1.3l-1.3 1.3-1.3-1.3h1.3M72.2 379.5l1.8 1.1-2.5 4.4-1.9-1zM68.1 382.3h2.5M73.1 382.3h2.6" fill="none" stroke="#840000" stroke-width=".26"/>
<path d="M105.2 144.6l.4 .4M105.6 144.2l-.5 .5M69 372.2v1.3l-.5-.1-.1-.7h.6M83.7 372.8h.5M84.4 372.2h-.7v1.3" fill="none" stroke="#006464" stroke-width=".26"/>
<path d="M119.4 150.5v4.1M120.9 150.5v4.1" fill="none" stroke="#840000" stroke-width=".51"/>
<path d="M48.3 381h7.6v12.7h-7.6z" fill="#ffffc2"/>
<g fill="none" stroke="#840000" stroke-width=".26">
<path d="M83.4 326l-.7 1.3M83.4 326v2.5M83.4 326l.8 1.3M43.2 382.3h5.1M43.2 392.4h5.1M43.2 384.8h5.1M43.2 387.4h5.1M43.2 389.9h5.1M48.3 381h7.6v12.7h-7.6zM55.9 382.3h5.1M55.9 392.4h5.1M55.9 384.8h5.1"/>
<path d="M55.9 387.4h5.1M55.9 389.9h5.1"/>
</g>
<path d="M85 323.7h.7l-.4 .5M85.5 324.2l.2 .3-.2 .5" fill="none" stroke="#006464" stroke-width=".26"/>
<path d="M80.5 318.4l.8 .8-1.8 1.7-.8-.7z" fill="#ffffc2"/>
<path d="M78.9 320.3l.5 .5-1.3 .8z" fill="#840000" stroke="#840000" stroke-width=".26"/>
<path d="M80.5 318.4l.8 .8-1.8 1.7-.8-.7zM78.1 321.6h.1" fill="none" stroke="#840000" stroke-width=".26"/>
<path d="M88.9 320.5a.79 .79 0 0 1 0 1.3" fill="none" stroke="#006464" stroke-width=".26"/>
<path d="M29.8 262.4h20.4v35.5h-20.4z" fill="#ffffc2"/>
<g fill="none" stroke="#840000" stroke-width=".26">
<path d="M61.2 50h1.3M62.5 49h5.1v2.1h-5.1zM67.6 50h1.2M29.8 262.4h20.4v35.5h-20.4zM32.4 276.4l.2-.5 .4-.2 .5 .2 .2 .5M49.1 267.2h1v.5h-1zM49.1 264.7h1.1v.5h-1.1zM49.1 279.9h1.1v.5h-1.1zM49.1 277.4h1.1v.5h-1.1zM49.1 272.3h1.1v.5h-1.1zM49.1 269.7h1.1v.6h-1.1zM50.2 264.9h5"/>
<path d="M50.2 270h5M50.2 277.6h5M50.2 267.5h5M50.2 272.5h5M63.1 273.8h2.1v5.1h-2.1zM64.1 272.5v1.3M64.1 278.9v1.3M71.4 273.8h2v5.1h-2zM72.4 272.5v1.3M72.4 278.9v1.3M32.4 284l.2 .4 .4 .2 .5-.2 .2-.4M32.4 297.9v5.1"/>
<path d="M39.8 296.9h.5v1h-.5zM40 297.9v5.1M49.1 295.1h1.1v.6h-1.1zM49.1 292.6h1.1v.5h-1.1zM49.1 285h1.1v.5h-1.1zM49.1 282.4h1.1v.6h-1.1zM50.2 282.7h5M50.2 292.9h5M50.2 285.2h5M50.2 280.2h5M50.2 295.4h5M68.6 281.4v1.3h1.2l-1.2 1.3-1.3-1.3h1.3"/>
<path d="M40 304.3v1.3h1.3l-1.3 1.2-1.3-1.2h1.3M42.7 338.1v1.2h1.2l-1.2 1.3-1.3-1.3h1.3M42.7 326v2.5M42.7 329.8v2.8M42.7 334.6v2.8M42.7 326l-.8 1.3M42.7 326l.7 1.3M83.4 338.2v1.3h1.3l-1.3 1.2-1.2-1.2h1.2M83.4 329.9v2.8M83.4 334.8v2.8"/>
</g>
<path d="M31.7 275a1.91 1.91 0 0 1 2-.4 1.91 1.91 0 0 1 1.2 1.8v7.6a1.91 1.91 0 0 1-1.9 1.9 1.91 1.91 0 0 1-1.9-1.9v-7.8zM37.5 279.7v1.2l2.5 2.6M40 275.8v10.2M42.5 278.4v1.3l-2.5 2.5M40.6 334.4h4.1M40.6 332.9h4.1M81.4 334.5h4.1M81.4 333h4.1" fill="none" stroke="#840000" stroke-width=".51"/>
<g fill="#840000" stroke="#840000" stroke-width=".26">
<path d="M32.4 284h1.3l-.2 .4-.5 .2-.4-.2z"/>
<path d="M32.4 276.4h1.3v7.6h-1.3z"/>
<path d="M32.6 275.9l.6-.1 .5 .6h-1.3z"/>
<path d="M40 273.3l1.3 2.5h-2.6z"/>
<path d="M41.9 277.1h1.3v1.3h-1.3z"/>
<circle cx="37.5" cy="279" r=".63"/>
<circle cx="40" cy="286" r="1.27"/>
</g>
<path d="M39.6 297.7v.8" fill="none" stroke="#a90000" stroke-width=".26"/>
<path d="M66.7 47.4l.4 .5M67.1 47l-.5 .5M60.4 260v1.2h.6M62.5 260h.8l-.4 .5 .4 .1v.5h-.8M63.7 260h.9l-.6 1.2M47.8 277.7h.9M58.8 260.8h1M61.4 261.2h.7M61.4 260.3l.3-.3v1.2M47.8 280.3h.9M45.1 323.7l-.4 1.3M95.5 334.9v.5" fill="none" stroke="#006464" stroke-width=".26"/>
<path d="M58.7 326.6h10.1v10.2h-10.1z" fill="#ffffc2"/>
<g fill="none" stroke="#840000" stroke-width=".26">
<path d="M365.6 96.1h1.3M366.9 95.1h5.1v2.1h-5.1zM372 96.1h8.9M375.8 94.9l2.5 1.2-2.5 1.3zM378.3 94.9v2.5M380.4 94.6v-.7h-.8h.8l-1.6 1.5M381.6 94.6v-.7h-.7h.7l-1.5 1.5M385.7 96.1h1.3v-1.2l1.2 1.2-1.2 1.3v-1.3M365.6 105.3h1.3M366.9 104.3h5.1v2h-5.1zM372 105.3h8.9M375.8 104l2.5 1.3-2.5 1.3z"/>
<path d="M378.3 104v2.6M380.4 103.8v-.8h-.8h.8l-1.6 1.5M381.6 103.8v-.8h-.7h.7l-1.5 1.5M385.7 105.3h1.3v-1.3l1.2 1.3-1.2 1.3v-1.3M369.2 122.7h1.3M369.2 131.8h1.3M370.5 121.7h5v2h-5zM370.5 130.8h5v2h-5zM375.5 122.7h8.9M375.5 131.8h8.9M379.3 121.4l2.6 1.3-2.6 1.3zM379.3 130.6l2.6 1.2-2.6 1.3z"/>
<path d="M381.9 121.4v2.6M381.9 130.6v2.5M383.9 121.2v-.8h-.7h.7l-1.5 1.5M383.9 130.3v-.8h-.7h.7l-1.5 1.6M385.2 121.2v-.8h-.8h.8l-1.5 1.5M385.2 130.3v-.8h-.8h.8l-1.5 1.6M389.3 122.7h1.2v-1.3l1.3 1.3-1.3 1.3v-1.3M389.3 131.8h1.2v-1.2l1.3 1.2-1.3 1.3v-1.3M56.1 329.2h2.6M56.1 331.7h2.6M58.7 326.6h10.1v10.2h-10.1zM61.2 336.8v2.5"/>
<path d="M63.8 336.8v2.5M68.8 329.2h2.6M68.8 331.7h2.6M363 366.6v3.9M363 378.1v3.8"/>
</g>
<path d="M70.1 324.9l.4 .6M70.3 324.2l.2 .3-.2 .4" fill="none" stroke="#006464" stroke-width=".26"/>
<path d="M162.7 362.8l1.8-1.7 .7 .7-1.8 1.8z" fill="#ffffc2"/>
<g fill="#840000" stroke="#840000" stroke-width=".26">
<path d="M162.8 363l.5 .5-1.2 .7z"/>
<path d="M363 384v1.3h.7l-.7 1.3-.8-1.3h.8z"/>
<path d="M256.8 367.9l1.3-.7v.7h1.2h-1.2v.8z"/>
<path d="M302.6 367.9h1.3v-.7l1.3 .7-1.3 .8v-.8z"/>
<path d="M214.2 387l.8 1.5h-1.5z"/>
</g>
<g fill="none" stroke="#840000" stroke-width=".26">
<path d="M215.9 193.8v2.8M215.9 198.6v2.8M385.4 239h5.1v2h-5.1zM426.3 231.1v1.3h1.3l-1.3 1.3-1.2-1.3h1.2M362.5 245.1h-3.3v1.3h1.2l-1.2 1.3-1.3-1.3h1.3M362.5 243.8h3.5M363.2 242.3h2.1M364.2 242.3v1.5M366 245.1h3.3M384.2 240h1.2M390.5 240h1.3M153.5 331.5v2.8"/>
<path d="M153.5 336.3v2.8M162.1 364.2h.1M162.7 362.8l1.8-1.7 .7 .7-1.8 1.8zM172.5 376.4h2.5M173.7 375.7l1.3 .7M175 376.4l-1.3 .8M194.3 376.9h2.5M194.3 376.9l1.3 .8M195.6 376.2l-1.3 .7M200.7 376.9h1.2M201.9 375.9h5.1v2.1h-5.1zM207 376.9h1.3"/>
<path d="M283 380h2v5.1h-2zM283 371.5h2v5.1h-2zM284 370.2v1.3M284 376.6v1.2M284 378.7v1.3M298.8 375.3v2.8M331.7 366.8v3.8M331.7 378.2v3.8M376 363.5v1.2h1.3l-1.3 1.3-1.2-1.3h1.2M398.4 365.4h2.8M403.2 365.4h2.8M168.7 383.8v2.8"/>
<path d="M168.7 388.6v2.8M214.2 386.5v2.5M214.2 387.7h2.6M214.2 385.2v5.1M215 387h-1.5l-.3 .2M284 385.1v1.2M298.8 380.1v2.8M331.7 384.2v1.2h1.3l-1.3 1.3-1.2-1.3h1.2M368.4 381.9h2.8M373.3 381.9h2.7v1.3h1.3l-1.3 1.2-1.2-1.2h1.2"/>
<circle cx="362.7" cy="245.1" r=".25"/>
<circle cx="365.8" cy="245.1" r=".25"/>
</g>
<g fill="none" stroke="#006464" stroke-width=".26">
<path d="M368.8 239.7a.81 .81 0 0 1 .5 .8 .81 .81 0 0 1-.5 .7M370 240.5l.7-.1 .1-.6-.8-.1v1.5M165.6 336.4v.6M177.3 364.4h.5M177.3 363.7l.4-.1 .2 .3-.6 .1M179.5 375.7l-.4 1.3M193.4 376.2l-.4 1.3M202 374.7l-.1 .3M210.2 373.5l-.3 1.3M255.1 367.2l.4 1.3 .4-1.3M308.8 367.2l.5 1.3 .4-1.3M329 373.4l.5-.9v1.3"/>
<path d="M330.7 373.5l-.2 .3-.5-.1M330.7 372.6h-.6a.53 .53 0 0 0 .6 .7v.1M331.8 375.6v1M374.1 377.7l.2 .2v.7M404.1 361.2l.2 .2v.7M202.9 389.5h.8M211.3 388.3h.8l-.4 .4 .4 .2v.4l-.2 .2h-.4M364.5 387.5l.5 1.3 .4-1.3"/>
</g>
<path d="M213.9 198.4h4M213.9 196.9h4M151.5 336h4.1M151.5 334.5h4.1M296.8 379.9h4.1M296.8 378.3h4.1M371.5 379.9v4M373 379.9v4M401.4 363.3v4.1M403 363.3v4.1M166.6 388.4h4.1M166.6 386.8h4.1" fill="none" stroke="#840000" stroke-width=".51"/>
<path d="M181.9 291.6h2.5v7.6h-2.5z" fill="#ffffc2"/>
<path d="M181.9 291.6h2.5v7.6h-2.5zM183.1 297.8h1.3v.3h-1.3zM183.1 295.3h1.3v.2h-1.3zM183.1 292.7h1.3v.3h-1.3zM184.4 295.4h5.1v-1.3l1.3 1.3-1.3 1.3v-1.3M184.4 292.9h3.8M184.4 297.9h3.8" fill="none" stroke="#840000" stroke-width=".26"/>
<path d="M292.6 356.7l1.8-1.7 .7 .7-1.7 1.8z" fill="#ffffc2"/>
<g fill="#840000" stroke="#840000" stroke-width=".26">
<path d="M292.7 356.9l.5 .5-1.2 .7z"/>
<path d="M276 378h1.5l-.8 1.5z"/>
<path d="M420 384.4v1.3h.8l-.8 1.3-.8-1.3h.8z"/>
<path d="M392.9 386v1.2h.8l-.8 1.3-.7-1.3h.7z"/>
</g>
<g fill="none" stroke="#840000" stroke-width=".26">
<path d="M215.9 202.7v1.3h1.3l-1.3 1.2-1.3-1.2h1.3M48.6 229.9v1.2h1.3l-1.3 1.3-1.2-1.3h1.2M49.9 222.3l-.8 1.2M49.9 222.3v2.5M49.9 222.3l.8 1.2M51.3 227.3h1.3M52.6 226.3h5.1v2h-5.1zM57.7 227.3h1.2M420 260.4v1.2h1.3l-1.3 1.3-1.3-1.3h1.3M232.4 314.5v1.2h1.3l-1.3 1.3-1.3-1.3h1.3M245.1 314.5v1.2h1.3l-1.3 1.3-1.3-1.3h1.3M390.5 306.1h2.8"/>
<path d="M395.4 306.1h2.7M292 358.1h.1M292.6 356.7l1.8-1.7 .7 .7-1.7 1.8zM363 359.9l-.8 1.3M363 359.9v2.6M363 359.9l.7 1.3M263.1 367.9h1.3M264.4 366.9h5.1v2h-5.1zM269.5 367.9h1.3M275.7 379.2l.3 .3h1.5M276.7 377.4v2.6M276.7 378.7h2.6"/>
<path d="M276.7 376.2v5.1M337.2 363.6h2.8M342 363.6h2.8v1.3h1.3l-1.3 1.2-1.3-1.2h1.3M368.4 363.5h2.8M373.3 363.5h2.7M392.9 361.8l-.7 1.3M392.9 361.8v2.6M392.9 368.6v3.8M392.9 380v3.8M392.9 361.8l.8 1.3M406 365.4v1.2h1.3l-1.3 1.3-1.3-1.3h1.3M420 360.3l-.8 1.3"/>
<path d="M420 360.3v2.5M420 367v3.8M420 378.5v3.8M420 360.3l.8 1.3M425.4 363.9h2.8M430.3 363.9h2.8M276.7 386.3v1.3h1.3l-1.3 1.3-1.2-1.3h1.2M398.4 383.8h2.8M403.2 383.8h2.8v1.3h1.3l-1.3 1.2-1.3-1.2h1.3M425.4 382.3h2.8M430.3 382.3h2.8"/>
</g>
<g fill="none" stroke="#006464" stroke-width=".26">
<path d="M51.7 220l-.4 1.2M56.8 224.7l.4 .5M57.2 224.3l-.5 .5M298.8 357.1l.4 1.2 .4-1.2M342.9 359.5l.2 .1v.7M365.4 357.6l-.4 1.3M374.1 359.3l.2 .2v.7M395.4 359.5l-.5 1.3M422.4 358l-.4 1.3M431.2 359.7l.1 .2v.7M273.8 379.2h.8l-.4 .5 .3 .1 .1 .5-.2 .2h-.4M404.1 379.6l.2 .2v.7"/>
<path d="M431.2 378.1l.1 .2v.7M265.4 380.5h.7M394.5 389.4l.4 1.3 .5-1.3M421.6 387.9l.4 1.2 .4-1.2"/>
</g>
<path d="M393.6 304v4.1M395.1 304v4.1M340.2 361.6v4M341.8 361.6v4M371.5 361.4v4.1M373 361.4v4.1M428.5 361.8v4.1M430 361.8v4.1M401.4 381.8v4M403 381.8v4M428.5 380.2v4.1M430 380.2v4.1" fill="none" stroke="#840000" stroke-width=".51"/>
<path d="M215.9 212.9h58.4v96.5h-58.4z" fill="#ffffc2"/>
<g fill="none" stroke="#840000" stroke-width=".26">
<path d="M510.2 31.8v1.2M510.2 38.1v1.3M43.2 50h2.5M43.2 52.6h2.5M74.5 53.2v2.6M74.5 58.3v2.5M91.7 50h2.5M99.3 45v2.5M99.3 52.6v2.5M422.9 47.2v1.3M426.7 40.9h-3.8v1.3M431.8 40.9h3.8v1.3"/>
<path d="M435.6 47.2v1.3M486.5 43.3h1.3M492.9 43.3h1.3M499 58.3v2.8M514.1 43.3h1.3M520.4 43.3h1.3M541.1 58.3h2.6M541.1 55.8h2.6M44.7 69.6h2.5M44.7 72.1h2.5M74.3 72.4v2.5M74.3 77.5v2.5"/>
<path d="M91.7 69.6h2.5M99.3 64.5v2.6M99.3 72.1v2.6M365.6 77.9h1.3M372 77.9h3.8M378.3 77.9h2.6M422.5 78.1h1.3M428.9 78.1h3.8M435.2 78.1h2.6M499 63.1v2.8M133.9 96.5h2.5M141.5 94h2.5"/>
<path d="M141.5 99.1h2.5M365.6 87h1.3M365.6 96.1h1.3M372 87h3.8M372 96.1h3.8M378.3 87h2.6M378.3 96.1h2.6M422.5 87.2h1.3M422.5 96.4h1.3M428.9 87.2h3.8M428.9 96.4h3.8M435.2 87.2h2.6"/>
<path d="M435.2 96.4h2.6M486.7 99.3h1.2M493 99.3h1.3M510.3 87.8v1.2M510.3 94.1v1.3M514.2 99.3h1.3M520.6 99.3h1.2M28.8 105.5h5.1M28.8 103h5.1M28.8 108.1h5.1M54.2 105.5h5.1M54.2 103h5.1"/>
<path d="M54.2 108.1h5.1M365.6 105.3h1.3M372 105.3h3.8M378.3 105.3h2.6M422.5 105.5h1.3M428.9 105.5h3.8M435.2 105.5h2.6M499.1 114.3v2.8M499.1 119.1v2.8M541.3 114.3h2.5M541.3 111.8h2.5M38 135.4h2.5"/>
<path d="M45.6 135.4h2.5M369.2 131.8h1.3M369.2 122.7h1.3M375.5 131.8h3.8M375.5 122.7h3.8M381.9 131.8h2.5M381.9 122.7h2.5M426.1 129.9h1.3M432.4 129.9h3.8M438.8 129.9h2.5M486.9 156h1.3M493.3 156h1.2"/>
<path d="M510.5 144.4v1.3M510.5 150.7v1.3M514.5 156h1.2M520.8 156h1.3M45.6 168h2.5M45.6 170.6h2.5M50.8 168h1.3M57.1 168h1.3M76.2 176.9h2.5M76.2 171.8h2.5M88.9 174.4h2.5M113.2 174.4h2.5"/>
<path d="M113.2 179.5h2.5M125.9 176.9h2.5M499.4 170.9v2.8M499.4 175.8v2.8M541.5 170.9h2.6M541.5 168.4h2.6M215.9 212.9h58.4v96.5h-58.4zM224.8 210.3v2.6M227.3 210.3v2.6M232.4 210.3v2.6M236.2 210.3v2.6M241.3 210.3v2.6"/>
<path d="M243.8 210.3v2.6M246.4 210.3v2.6M248.9 210.3v2.6M251.5 210.3v2.6M254 210.3v2.6M257.8 210.3v2.6M261.6 210.3v2.6M274.3 217.9h2.6M46.1 227.3h2.5M46.1 229.9h2.5M51.3 227.3h1.3M57.7 227.3h1.2"/>
<path d="M76.7 236.2h2.5M76.7 231.1h2.5M89.4 233.7h2.5M113.7 238.8h2.5M113.7 233.7h2.5M126.4 236.2h2.5M213.4 233.2h2.5M213.4 235.7h2.5M213.4 238.3h2.5M213.4 229.4h2.5M274.3 228.1h2.6M274.3 230.6h2.6"/>
<path d="M274.3 233.2h2.6M274.3 220.5h2.6M274.3 235.7h2.6M274.3 238.3h2.6M420 235v2.5M541.7 235.8h2.5M541.7 233.3h2.5M213.4 240.8h2.5M213.4 244.6h2.5M274.3 248.4h2.6M274.3 251h2.6M274.3 253.5h2.6"/>
<path d="M274.3 240.8h2.6M274.3 243.3h2.6M274.3 245.9h2.6M359.2 245.1h2.5M366.8 245.1h2.5M409.8 245.1h2.6M409.8 240h2.6M409.8 247.7h2.6M409.8 250.2h2.6M409.8 242.6h2.6M409.8 252.7h2.6M420 257.8v2.6"/>
<path d="M50.2 264.9h5M50.2 270h5M50.2 277.6h5M50.2 267.5h5M50.2 272.5h5M64.1 272.5v1.3M64.1 278.9v1.3M213.4 263.7h2.5M213.4 268.7h2.5M274.3 263.7h2.6M274.3 266.2h2.6M274.3 276.4h2.6"/>
<path d="M274.3 278.9h2.6M32.4 297.9v5.1M40 297.9v5.1M50.2 292.9h5M50.2 295.4h5M50.2 282.7h5M50.2 285.2h5M50.2 280.2h5M184.4 292.9h3.8M184.4 295.4h3.8M184.4 297.9h3.8M213.4 292.9h2.5"/>
<path d="M213.4 295.4h2.5M213.4 281.4h2.5M274.3 281.4h2.6M274.3 286.5h2.6M274.3 296.7h2.6M274.3 299.2h2.6M541.8 292.7h2.5M541.8 290.2h2.5M232.4 309.4v2.5M245.1 309.4v2.5M274.3 301.8h2.6M274.3 304.3h2.6"/>
<path d="M390.5 316.2h2.8M395.4 316.2h2.7M409.6 307.3v1.3M500 358.1h.1M511 349.8h2.6M511 344.7h2.6M523.7 347.2h2.6M542 349.8h2.6M542 347.2h2.6M91.4 379.7v2.8M102.7 379.7v2.8M113 379.7v2.8"/>
<path d="M157.1 378.8v1.3M224.8 379.3v1.3M337.2 363.6h2.8M342 363.6h2.8M363 366.6v3.9M363 378.1v3.8M368.4 363.5h2.8M373.3 363.5h2.7M392.9 368.6v3.8M392.9 380v3.8M398.4 365.4h2.8M403.2 365.4h2.8"/>
<path d="M420 367v3.8M420 378.5v3.8M425.4 363.9h2.8M430.3 363.9h2.8M446.7 367.3v3.8M446.7 378.7v3.8M452.1 364.1h2.8M456.9 364.1h2.8M43.2 382.3h5.1M43.2 392.4h5.1M43.2 384.8h5.1M43.2 387.4h5.1"/>
<path d="M43.2 389.9h5.1M55.9 382.3h5.1M55.9 392.4h5.1M55.9 384.8h5.1M55.9 387.4h5.1M55.9 389.9h5.1M67.9 392.4h2.6M68.1 382.3h2.5M73 392.4h5.1M73.2 382.3h5M80.6 392.4h2.6M80.8 382.3h2.5"/>
<path d="M91.4 384.6v5.5M91.4 392.2v2.8M102.7 384.6v5.5M102.7 392.2v2.8M113 384.6v5.5M113 392.2v2.8M157.1 385.2v1.3M157.1 387.4v1.2M157.1 393.7v1.3M168.7 383.8v2.8M168.7 388.6v2.8M224.8 385.7v1.3"/>
<path d="M224.8 387.9v1.2M224.8 394.2v1.3M236.3 384.3v2.8M236.3 389.1v2.8M368.4 381.9h2.8M373.3 381.9h2.7M398.4 383.8h2.8M403.2 383.8h2.8M425.4 382.3h2.8M430.3 382.3h2.8M452.1 382.5h2.8M456.9 382.5h2.8"/>
</g>
<path d="M250.1 255.5l.6 1.7M250.7 257.2l-.3 .6-.3 .2M251.2 259.7h.2a1.59 1.59 0 0 1 0 2.6h-.2M251.3 255.5l-.6 1.7" fill="none" stroke="#840000" stroke-width=".32"/>
<g fill="none" stroke="#006464" stroke-width=".26">
<path d="M434.1 38.5h.7M434.1 37.6l.3-.4v1.3M512 26.9l-.4 1.3M85.3 57.5l-.3 1.3M111.6 51.6h.9M420.1 44.1h.7M424.4 52h.8l-.4 .4M425 52.4l.2 .3-.2 .5M437.1 52h.8l-.4 .4M437.7 52.4l.2 .3-.2 .5M85.1 76.7l-.3 1.3M111.6 71.2h.9"/>
<path d="M436.4 72.4h.7M512.1 82.9l-.4 1.3M514.9 90.9h.7M47.6 130a.81 .81 0 0 1 .6 .7 .81 .81 0 0 1-.6 .8M48.8 130.8l.7-.1 .1-.6-.8-.1v1.5M51.3 160.7l-.4 1.2M56.3 165.4l.4 .5M56.7 165l-.5 .5M79.3 171.9h.9M116.2 174.5h1M125.9 170.3l.4-.9v1.3M127.6 169.5h-.7a.53 .53 0 0 0 .6 .7v.4h-.6"/>
<path d="M553.7 167.1h.7M51.7 220l-.4 1.2M56.8 224.7l.4 .5M57.2 224.3l-.5 .5M79.8 231.2h.9M116.7 233.8h1M126.4 229.6l.4-.9v1.3M128.1 228.8l-.7 .1a.53 .53 0 0 0 .6 .6v.4h-.6M225.1 236.3h.7M368.8 239.7a.81 .81 0 0 1 .5 .8 .81 .81 0 0 1-.5 .7M425.1 236.5h.7M433.7 237.6l.4 .1"/>
<path d="M433.9 238.3l.2 .2-.2 .4M60.4 260v1.2h.6M62.5 260h.8l-.4 .5 .4 .1v.5h-.8M63.7 260h.9l-.6 1.2M272.2 256.6h.8M370 240.5l.7-.1 .1-.6-.8-.1v1.5M419.1 244.3a1.49 1.49 0 0 1 0 1.8M420.1 247.3v.9M47.8 277.7h.9M58.8 260.8h1M61.4 261.2h.7M61.4 260.3l.3-.3v1.2"/>
<path d="M47.8 280.3h.9M272.2 282h.8M272.2 299.8h.8M254.2 312.8a.79 .79 0 0 1 0 1.3M432.8 306.7l.3 .2 .1 .3-.5 .2M432.8 306.1l.4 .1M433.8 306.1v1.3M342.9 359.5l.2 .1v.7M374.1 359.3l.2 .2v.7M431.2 359.7l.1 .2v.7M456.8 358.4h.7M457.8 360l.2 .1v.7"/>
<path d="M509.7 357.1v1.1l.2 .1M514.1 344.8h1M69 372.2v1.3l-.5-.1-.1-.7h.6M82.7 378.6h.3l.3 .2-.1 .8-.5 .3M83.3 379.1l-.3 .3-.3-.1M83.7 372.8h.5M84.4 372.2h-.7v1.3M93.9 374.9l-.5 1.3M374.1 377.7l.2 .2v.7M404.1 361.2l.2 .2v.7M404.1 379.6l.2 .2v.7M431.2 378.1l.1 .2v.7"/>
<path d="M457.8 378.4l.2 .2v.6M69.2 399.2v1.3M69.2 399.7h-.3l-.3 .2 .2 .5h.4M81.9 388.8l.4-.1 .2 .3-.1 .7-.5 .3M82.5 389.3l-.2 .2h-.4M84 399.8h.4M84.6 399.2h-.6v1.3M93 398.4l.4 1.3 .5-1.3M110.1 392.1l.2 .2v.7M110.1 384.5l.2 .2v.6M118.8 382.9h.7M120.4 392.1l.1 .2v.7"/>
<path d="M120.4 384.5l.1 .2v.6"/>
</g>
<path d="M214.9 240.4h.7M214.9 268.3h.7M275.8 278.5h.8M39.6 297.7v.8M275.8 303.9h.8" fill="none" stroke="#a90000" stroke-width=".26"/>
<g fill="none" stroke="#0f0f0f" stroke-width=".26">
<path d="M114.5 39.5h.5M115.3 39.4l.4-.3v1.2M420.4 31.1h.7M420.6 30l.1-.2v1.3M447.8 29.8l.2 .2-.1 .3-.7 .8h.8M114.7 40.3h.3M115.3 40.3h.7M485.2 57.9h.7M115.3 60.8l.5-.1 .2 .3-.7 .9h.7M359.1 77.4h.7M360.2 85.4l.1 .4-.7 .8h.7M419.8 96h.8"/>
<path d="M419.9 86.8h.7M420.6 94.8v.4M366.7 121l.3 .2-.1 .3-.7 .8h.8M366.7 131.4h.8M367 130.3l.1-.2v1.3M516.4 143.4v.5M308.5 219.6h1M348.9 203.9l.3 .1M349 204.6h.2v.5l-.3 .1M145.6 235.8h.7M207.6 235.3h.7M291 227.7h.8"/>
<path d="M291.3 226.6l.1-.2v1.3M291.5 228.9l.3 .3-.1 .3-.7 .7h.8M291.6 236.6l.1 .5-.7 .7h.8M487.1 234.1v1.1l.2 .2M487.7 235.4h.7M487.7 234.5l.4-.4v1.3M290.2 247.1h.5M290.4 247.9l.3 .1M291 249.4l.5-.1 .3 .3-.8 .9h.8M291 240.4h.8M291 248h.8M291 247.1l.4-.4v1.3"/>
<path d="M291 258.1h.8M291.7 259.5v.5M401.5 247.2h.7M290.4 270.7l.2 .1M290.4 268.1l.2 .2M290.4 272.1v1.1l.2 .2M291 267h.8l-.5 .5 .4 .1v.6h-.7M291 260.7h.8M291 269.7l.5-.1 .3 .3-.8 .9h.8M291 272.5l.4-.4v1.3M291 273.4h.8M63.7 280.9h.9"/>
<path d="M291 298.8h.8M291 281h.8M294 291.2h.7M294.2 290.1l.1-.2v1.3M294.6 287.4l.2 .2-.1 .3-.7 .7h.8M487.2 292.1l.2 .2M487.8 291.2l.5-.2 .3 .4-.8 .9h.8M164.1 328.4h.3M164.2 329.1h.2v.4l-.3 .1M340.4 353.9l.3 .1M340.5 354.6h.2v.5l-.3 .1M487.5 349.3h.2"/>
<path d="M488 348.1h.8l-.4 .4 .3 .2v.5h-.7M246.1 376v.4"/>
</g>
<g fill="none" stroke="#0000c2" stroke-width=".26">
<path d="M471.2 19.8h102.6v54.7h-102.6zM433.6 23.4v.8M433.6 23.5l.5-.1 .1 .8M444.4 23.4v.8M444.7 23.4l-.3 .2M475.6 25.4h51.1v21.2h-51.1zM484.8 26.8l.3 .1 .1 .8M485.2 27.6l-.4 .1M485.2 27.1l-.4 .1M485.8 26.4v1.1l.2 .2M486.4 27.3l.6-.2-.1-.2-.3-.1-.2 .2 .1 .6h.4M492.5 27.2h1"/>
<path d="M494 26.4h.7l-.4 .5 .4 .1v.6h-.7M496.3 27.2h.9M497.8 26.8l1 .4-1 .4M505.3 26.4h-.6v.6l.6-.1v.7h-.6M509.7 23.3h.4M509.9 22.6l.3 .9M511 22.6v.9l-.5-.9v.9M511.9 22.9l-.6 .6h.6M512.8 22.6l-.3 .4h.2v.4h-.5M513.1 22.6v.4h.4l.1 .3-.2 .2-.3-.1M514 23.5h.1M514.4 23l.5 .1-.1 .4h-.4"/>
<path d="M514.4 22.9v.9M515.3 23h.3M515.3 23h-.1M515.6 22.6v.9l-.4-.1v-.4M515.9 22.9h.4M516.1 22h.4v-.5h-.4v.9M516.3 22.6l-.2 .1v.8M516.9 21.2l.4 .1-.2 .4M517 22h.1M517.1 22h-.1M517.6 21.5h.3M517.7 21.2v.7l.2 .2"/>
<path d="M518.2 21.6h.7M518.2 21.8h.7M519.4 21.2h.3l.1 .2-.5 .7h.5M519.4 21.2h-.1M520.2 22h.4M520.6 21.2h-.4v.4l.4-.1v.5M520.6 22h.1M521 21.2h.5l-.3 .3 .3 .1v.4M521 22h.5M521.5 22h.1M522 22h.1M522 21.2v.8"/>
<path d="M522 21.2h.1a.44 .44 0 0 1 .3 .4 .44 .44 0 0 1-.4 .4M522 21.2h.1M522.9 21.2l-.2 .7 .2 .2 .3-.1v-.5l-.5 .2M522.9 21.2h.1M523.2 21.2h-.3M524 21.2h-.4M524 21.2h.1M524.1 21.2v.3l-.5 .6h.5M486.7 49h21.8v23.1h-21.8zM489.7 50.4h.4M490 50h.1M496.8 50.4h.7l-.7 .9h.7"/>
<path d="M471.3 75.8h102.6v54.8h-102.6zM42.5 90v.1M42.5 89.3v.2M54.3 89.3l-.1 1.2M54.3 89.3h-.4l-.2 .2 .1 .6h.5M63.6 91.3v.9M63.8 91.3l-.2 .1M67.7 90.1l-.1 .2M77.9 89.3l.2 .8M82.2 88.9v1.2M82.6 89.3l-.4 .1M87.5 88.9v1l.2 .2"/>
<path d="M92.9 89.7l.6-.1v-.3h-.4l-.2 .2 .1 .6h.5M475.7 81.4h51.1v21.2h-51.1zM484.9 82.8l.4 .2v.7M485.3 83.6l-.4 .1M485.3 83.1l-.4 .1M485.9 82.4v1.1l.2 .2M486.5 83.3l.6-.2v-.2l-.4-.1-.2 .2 .1 .6h.5M492.6 83.2h1M494.1 82.4h.8l-.4 .5 .3 .1v.6h-.7M496.4 83.2h1M498 82.8l.9 .4-.9 .4M505.5 82.4h-.6l-.1 .6h.6l.1 .6h-.7"/>
<path d="M486.8 105h21.8v23.1h-21.8zM489.8 106.5h.5M490.1 106h.2M471.6 132.5h102.6v54.7h-102.6zM476 138h51v21.3h-51zM485.2 139.5l.4 .2v.6M485.6 139.8h-.4M486.2 139.1v1l.2 .2M486.8 139.9l.6-.1-.1-.3h-.3l-.2 .2v.6h.5M492.9 139.8h1M494.3 139.1h.8l-.4 .4 .4 .2v.5h-.8M496.6 139.8h1"/>
<path d="M498.2 139.5l1 .3-1 .4M505.7 139.1h-.6l-.1 .6 .7-.1v.6h-.7M32.8 140.8h114.6v44.2h-114.6zM42.3 143.1l-.1 .2M54.7 141.8h-.6v.7l.6-.1v.6h-.6M60.5 141.9l-.1 .4 .1 .8M64.9 141.8h.8l-.4 .5M65.6 142.5v.5M67.1 142.3l.2 .8 .3-.6M72 142.3h.5M72.5 142.6l-.6 .2 .2 .3h.4M100.3 150.2l.2-.5 .2 .5"/>
<path d="M100.4 150h.2M100.8 150.2h.1M100.9 150.2h.1M100.9 150.2h-.1M485.6 140.3h-.4M56.7 169.5l.2 .5M67.1 162.2h.5M67.4 163h.2M71.1 173.6h.5M71.3 174.4l.3 .1M487 161.7h21.9v23.1h-21.9zM490 163.1h.5"/>
<path d="M490.4 162.7h.1M497.2 163.1h.6l-.6 .8h.6M32.9 199.1h114.8v44.2h-114.8zM190.6 197.6h.5M190.8 197.2v1.2M193.6 197.6v1.3M193.6 198.4l.4 .1M194 197.6l-.4 .1M197.7 197.1l-.3 .9h.8M200.9 197.7l.3-.1 .3 .3-.1 .4-.5 .1M203.7 197.2h.5l.2 .2-.1 .4-.6 .1M204 197.9l.4 .6"/>
<path d="M302.3 198.9h.5M302.5 198.5v1.2M305.3 198.9v1.3M305.3 199.7h.4M305.7 198.9l-.4 .1M309.4 198.4l-.3 .9h.8M312.6 199l.3-.1 .3 .2-.1 .6h-.5M315.4 198.5h.5l.2 .2-.1 .4h-.6M315.7 199.1l.4 .6M471.7 197.4h102.6v54.7h-102.6zM478.5 198.4v1.1l.2 .1M107 201.4l-.1 .2"/>
<path d="M119.4 200.1h-.6v.6h.6v.6h-.6M125.2 200.3v1M129.6 200.1h.8l-.4 .5M130.3 200.7v.7M131.8 200.6l.2 .8 .3-.6M136.7 200.6h.5M137.2 200.9l-.6 .2 .2 .3h.4M322.3 215.4l-.2 .1M322.3 215.8l-.2 .1 .2 .3M326.6 215.4l-.5 .2v.5l.5 .1M331.9 215.4h.5M332.1 215v1.1l.3 .1"/>
<path d="M335 215h.4l.3 .2-.1 .4h-.6M335.3 215.6l.4 .6M476.1 202.9h51.1v21.3h-51.1zM481.5 204.4h.4l.1 .3-.7 .1M481.9 205.2h-.4M487.9 204h.8l-.4 .4 .4 .2v.5h-.8M490.2 204.7h1M491.8 204.4l1 .3-1 .4M497.1 204h.6M497.6 204.4l.2 .3-.2 .5M471.8 254.3h102.6v54.7h-102.6zM476.2 259.8h51.1v21.3h-51.1z"/>
<path d="M478.7 255.3v1l.1 .2M481.7 261.3h.3l.1 .3-.6 .1M482 262.1h-.3M488.1 260.8h.8l-.5 .5 .4 .2v.5h-.7M490.4 261.6h.9M491.9 261.3l1 .3-1 .4M497.3 260.8h.6M497.7 261.3l.2 .3-.2 .5M415.8 291.5v2.2l.3 .4M472.1 311.3h102.6v54.7h-102.6zM476.5 316.9h51.1v21.2h-51.1zM478.9 312.3v1.1l.2 .2"/>
<path d="M481.9 318.3l.4 .1v.2l-.6 .1M482.3 319.1h-.4M488.3 317.9h.8l-.4 .5 .3 .1v.5h-.7M490.6 318.7h1M492.2 318.3l1 .4-1 .3M497.5 317.9h.6M497.9 318.4l.3 .2-.3 .5M453.7 325.7l.2-.1a.62 .62 0 0 1 .5 .7 .62 .62 0 0 1-.6 .5l-.2-.4zM454.9 326.2h.4M455.5 325.6h-.6v1.3M455.9 325.6h.7l-.4 .5 .4 .1v.5h-.7M457.3 325.7l.1-.1a.62 .62 0 0 1 .5 .7 .62 .62 0 0 1-.6 .5l-.2-.4z"/>
<path d="M459.3 325.5l-1.1 1.7M460.5 325.7a.56 .56 0 0 0-.8 .5 .56 .56 0 0 0 .8 .5M460.9 325.7l.5-.1 .3 .4-.8 .9h.8M462.9 326.1l-.3 .3-.3-.1-.1-.6 .4-.1 .3 .2-.1 .8-.5 .3M463.5 325.7l.2-.1a.62 .62 0 0 1 .4 .7 .62 .62 0 0 1-.6 .5l-.1-.4zM464.6 326.9h.7M464.6 326l.3-.4v1.3M466.4 325.6l-.6 .3v.7l.2 .3 .4-.2v-.6h-.4l-.2 .2M467.7 325.6h-.7v.6l.6-.1 .1 .6h-.7M468.2 326.9h.7M468.2 326l.4-.4v1.3M170.6 371.7l.4 1.3"/>
<path d="M238.3 372.2l.4 1.3M152 388.2l.4 1.3M219.7 388.7l.4 1.3M513.2 403h.7"/>
</g>
<g fill="none" stroke="#009600" stroke-width=".26">
<path d="M410.5 31.5h12.3l.1 9.4M435.5 31.5h1.9M435.6 31.5v9.4M510.2 39.4v13.8M45.7 50h15.5M68.8 50h22.9M74.5 50v3.2M99.3 40.8v4.2M472.8 58.3h14.8M494.2 43.3h4.8M495.2 58.3h15v12.1h4.7M506.6 43.3h7.5"/>
<path d="M521.7 43.3h3.7v12.5h4.6M537.6 55.8h3.5M47.2 69.6h14M68.8 69.6h22.9M74.3 69.6v2.8M99.3 62.4v2.1M345.9 77.9h19.7M380.9 77.9h4.8M406 78.1h16.5M437.8 78.1h4.8M346.5 87h19.1M347.3 96.1h18.3"/>
<path d="M380.9 96.1h4.8M380.9 87h4.8M406 87.2h16.5M406 96.4h16.5M437.8 87.2h4.8M437.8 96.4h4.8M494.3 99.3h4.8M506.7 99.3h7.5M510.3 95.4v13.8M521.8 99.3h3.7v12.5h4.6M27.1 108.1h1.7M59.3 105.5h2.9"/>
<path d="M348.2 105.3h17.4M380.9 105.3h4.8M406.1 105.5h16.4M437.8 105.5h4.8M472.9 114.3h14.8M495.3 114.3h15M537.7 111.8h3.6M48.1 135.4h3.7M349.5 122.7h19.7M350 131.8h19.2M384.4 131.8h4.9M384.4 122.7h4.9"/>
<path d="M406.9 129.9h19.2M441.3 129.9h4.9M94.5 147.2h5.2M107.3 147.2h4.6v27.2M116.3 152.5h-47.8v11.7M124 152.5h6.9v24.4M494.5 156h4.9M507 156h7.5M510.5 152v13.9M522.1 156h3.7v12.4h4.6M48.1 168h2.7M48.1 165.5h1.4"/>
<path d="M58.4 168h6.2M68.5 171.8h7.7M79.9 161h-4.1v10.8M87.5 161h4.8v13.4M91.4 174.4h8.9M107.9 174.4h5.3M111.9 163.4h3.9M123.4 163.4h7.5M128.4 176.9h4.8M130.9 168.1h4.7M215.9 177.3v1.3M224.8 176v34.3"/>
<path d="M235.7 173.6v3.7h-31.2v1.3M261.6 176v21.6h-25.4v12.7M261.6 177.3h77.5v1.3M270.5 177.3v1.3M281.9 177.3v1.3M293.4 177.3v1.3M304.8 177.3v1.3M316.2 177.3v1.3M327.7 177.3v1.3M473.2 170.9h14.7M495.6 170.9h14.9M538 168.4h3.5"/>
<path d="M204.5 186.2v2.5M215.9 186.2v1.3h-11.4M224.8 197.6h7.6v12.7M224.8 192.5h-8.9v1.3M227.3 197.6v12.7M241.3 197.6v12.7M243.8 197.6v12.7M246.4 197.6v12.7M248.9 197.6v12.7M251.5 197.6v12.7M254 197.6v12.7M257.8 197.6v12.7"/>
<path d="M261.6 192.5h8.9v1.3M270.5 186.2v2.5h68.6M281.9 186.2v2.5M293.4 186.2v2.5M304.8 186.2v2.5M316.2 186.2v2.5M327.7 186.2v2.5M339.1 186.2v3.8M356.5 199.3v-1.3h-17.4v7.6M95 206.5h5.2M107.8 206.5h4.6v27.2M116.8 211.8h-47.8v11.7"/>
<path d="M124.5 211.8h6.9v24.4M215.9 201.4v1.3M270.5 201.4v1.3M288.3 212.9h-5.1v5h-6.3M295.9 212.9h14M340.2 205.6h-66v4.7h-12.6M356.5 206.9v3.8M420 219.7v15.3M48.6 224.8h1.3M48.6 227.3h2.7M58.9 227.3h6.3M69 231.1h7.7"/>
<path d="M80.4 220.3h-4.1v10.8M88 220.3h4.8v13.4M91.9 233.7h8.9M108.5 233.7h5.2M112.4 222.8h3.9M124 222.8h7.4M128.9 236.2h4.8M199.4 238.3h14M199.4 235.7h14M199.4 233.2h14M199.4 229.4h14M276.9 238.3h15.2"/>
<path d="M276.9 230.6h15.2M276.9 220.5h11.4M276.9 235.7h15.2M276.9 228.1h15.2M276.9 233.2h15.2M295.9 220.5h14M404.7 233.7h-.2v6.3M420 221h6.3v1.3M420 224.8h-15.3v1.3M426.3 229.9v1.2M473.3 235.8h37.4M494.7 220.9h4.8"/>
<path d="M507.1 220.9h7.5M510.7 220.9v9.9M522.2 220.9h3.7v12.4h4.6M538.1 233.3h3.6M199.4 240.8h14M199.4 244.6h14M276.9 253.5h15.2M276.9 256h15.2M276.9 251h15.2M276.9 240.8h15.2M276.9 243.3h15.2M276.9 245.9h15.2"/>
<path d="M276.9 248.4h15.2M276.9 258.6h15.2M384.2 240h-.5v5.1h-14.4M391.8 240h18M393.3 252.7h16.5M393.3 247.7h16.5M393.3 250.2h16.5M393.3 245.1h16.5M398.4 242.6h11.4M55.2 270h17.2v2.5M55.2 272.5h8.9M55.2 277.6h.7v4.2h9.1"/>
<path d="M199.4 268.7h14M199.4 263.7h14M276.9 268.7h15.2M276.9 271.3h15.2M276.9 273.8h15.2M276.9 278.9h15.2M276.9 276.4h15.2M276.9 266.2h15.2M276.9 261.1h15.2M276.9 263.7h15.2M494.8 277.7h4.8M507.2 277.7h7.5"/>
<path d="M510.8 277.7v10M522.4 277.7h3.6v12.5h4.6M55.2 280.2h.7M55.2 282.7h.7v5.3h8.9M55.2 285.2h.7M64.1 280.2h8.3M68.6 280.2v1.2M188.2 292.9h25.2M199.4 281.4h14M213.4 295.4h-14v2.5h-11.2M276.9 286.5h15.2M276.9 289.1h18.2"/>
<path d="M276.9 296.7h15.2M276.9 284h15.2M276.9 281.4h15.2M276.9 291.6h18.1M276.9 299.2h15.2M473.5 292.7h37.3M538.2 290.2h3.6M32.4 303v.7h7.6v.6M232.4 311.9v2.6M245.1 311.9v2.6M276.9 301.8h15.2M276.9 304.3h15.2"/>
<path d="M388 316.2h2.5M390.5 306.1h-2.5v12.7M398.1 316.2h25.4M398.1 306.1h43.2M409.6 306.1v1.2M409.6 315v1.2M431.2 316.2h10.1M42.7 329.2h13.4M42.7 328.5v1.3M42.7 337.4v.7M54.1 329.2v2.5h2M61.2 339.3v3h2.6v-3"/>
<path d="M71.4 329.2h12M74.3 329.2v2.5h-2.9M78.1 321.6v7.6M83.4 328.5v1.4M83.4 337.6v.6M112.8 330.7h13.4M112.8 330.1v1.2M112.8 339v.6M124.2 330.7v2.5h2M141.5 330.7h12M144.4 330.7v2.5h-2.9M149.7 322.8v7.9"/>
<path d="M153.5 339.1v.6M155.4 330.1h-1.9v1.4M495 334.8h4.9M507.5 334.8h7.5M511 334.8v9.9M522.6 334.8h3.7v12.4h4.6M131.3 340.9v2.9h2.6v-2.9M292 358.1v9.8M331.7 355.6v11.2M473.7 349.8h37.3M498.1 349.8v8.3h1.9M538.5 347.2h3.5"/>
<path d="M113 379.7h-29.7v2.6M129.2 376.4h3.8M140.6 376.4h6v8.3M146.6 376.6h22.1M157.1 376.6v2.2M162.1 364.2v12.4M172.5 376.4h-3.8v7.4M196.8 376.9h3.9M208.3 376.9h5.9v8.3M214.2 377.1h22.1M224.8 377.1v2.2M229.7 364.7v12.4"/>
<path d="M240.2 376.9h-3.9v7.4M259.3 367.9h3.8M270.8 367.9h31.8M276.7 367.9v8.3M284 367.9v2.3M284 377.8v.9h-4.7M298.8 367.9v7.4M331.7 363.6h5.5M363 362.5v4.1M363 363.5h5.4M392.9 365.4h5.5M392.9 364.4v4.2"/>
<path d="M420 362.8v4.2M420 363.9h5.4M446.7 364.1h5.4M446.7 363.1v4.2M43.2 382.3v-3.8h17.8v3.8h7.1M43.2 392.4v2.7h17.8v-2.7h6.9M43.2 387.4h-2.7v11.1h23v-11.1M43.2 384.8v5.1M61 384.8v5.1M61 387.4h52.5M83.2 392.4v2.6h29.8M146.6 389.8v5l22.1 .2v-3.6"/>
<path d="M157.1 386.5v.9l-8-.2M214.2 390.3v5.1l22.1 .1v-3.6M224.8 387v.9l-8-.2M276.7 381.3v5h22.1v-3.4M331.7 382v2.2M368.4 381.9h-5.4v2.1M398.4 383.8h-5.5v2.2M425.4 382.3h-5.4v2.1M452.1 382.5h-5.4v2.2"/>
</g>
<g fill="none" stroke="#000084" stroke-width=".26">
<path d="M45.1 46.9l1.2 1.2M46.3 46.9l-1.2 1.2M540.5 52.6l1.3 1.2M541.8 52.6l-1.3 1.2M46.6 66.4l1.3 1.3M47.9 66.4l-1.3 1.3M28.2 102.4l1.2 1.2M29.4 102.4l-1.2 1.2M58.7 102.4l1.2 1.2M59.9 102.4l-1.2 1.2M540.7 108.6l1.2 1.2M541.9 108.6l-1.2 1.2"/>
<path d="M540.9 165.3l1.2 1.2M542.1 165.3l-1.2 1.2M541 230.1l1.3 1.3M542.3 230.1l-1.3 1.3M41.2 273.3l1.2 1.2M42.4 273.3l-1.2 1.2M54.6 266.9l1.3 1.2M54.6 264.3l1.3 1.2M55.9 266.9l-1.3 1.2M55.9 264.3l-1.3 1.2M54.6 294.8l1.3 1.2M54.6 292.3l1.3 1.2"/>
<path d="M55.9 294.8l-1.3 1.2M55.9 292.3l-1.3 1.2M541.2 287l1.2 1.3M542.4 287l-1.2 1.3M136.6 335.9l1.2 1.3M137.8 335.9l-1.2 1.3M541.4 344.1l1.2 1.2M542.6 344.1l-1.2 1.2"/>
</g>
<g fill="#009600" stroke="#009600" stroke-width=".26">
<circle cx="254" cy="197.6" r=".46"/>
<circle cx="261.6" cy="192.5" r=".46"/>
<circle cx="257.8" cy="197.6" r=".46"/>
<circle cx="248.9" cy="197.6" r=".46"/>
<circle cx="251.5" cy="197.6" r=".46"/>
<circle cx="276.7" cy="386.3" r=".46"/>
<circle cx="292" cy="367.9" r=".46"/>
<circle cx="298.8" cy="367.9" r=".46"/>
<circle cx="284" cy="378.7" r=".46"/>
<circle cx="284" cy="386.3" r=".46"/>
<circle cx="276.7" cy="367.9" r=".46"/>
<circle cx="284" cy="367.9" r=".46"/>
<circle cx="331.7" cy="363.6" r=".46"/>
<circle cx="420" cy="382.3" r=".46"/>
<circle cx="392.9" cy="383.8" r=".46"/>
<circle cx="363" cy="381.9" r=".46"/>
<circle cx="168.7" cy="376.6" r=".46"/>
<circle cx="214.2" cy="395.4" r=".46"/>
<circle cx="157.1" cy="376.6" r=".46"/>
<circle cx="227.3" cy="197.6" r=".46"/>
<circle cx="241.3" cy="197.6" r=".46"/>
<circle cx="224.8" cy="197.6" r=".46"/>
<circle cx="224.8" cy="387.9" r=".46"/>
<circle cx="214.2" cy="377.1" r=".46"/>
<circle cx="224.8" cy="377.1" r=".46"/>
<circle cx="229.7" cy="377.1" r=".46"/>
<circle cx="236.3" cy="377.1" r=".46"/>
<circle cx="224.8" cy="395.5" r=".46"/>
<circle cx="510.2" cy="43.3" r=".46"/>
<circle cx="422.8" cy="31.5" r=".46"/>
<circle cx="435.6" cy="31.5" r=".46"/>
<circle cx="499" cy="58.3" r=".46"/>
<circle cx="525.4" cy="55.8" r=".46"/>
<circle cx="510.2" cy="58.3" r=".46"/>
<circle cx="525.5" cy="111.8" r=".46"/>
<circle cx="499.1" cy="114.3" r=".46"/>
<circle cx="510.3" cy="99.3" r=".46"/>
<circle cx="435.6" cy="40.9" r=".46"/>
<circle cx="422.9" cy="40.9" r=".46"/>
<circle cx="510.7" cy="220.9" r=".46"/>
<circle cx="525.8" cy="168.4" r=".46"/>
<circle cx="499.4" cy="170.9" r=".46"/>
<circle cx="510.5" cy="156" r=".46"/>
<circle cx="55.9" cy="285.2" r=".46"/>
<circle cx="68.6" cy="280.2" r=".46"/>
<circle cx="55.9" cy="280.2" r=".46"/>
<circle cx="112.4" cy="222.8" r=".46"/>
<circle cx="112.4" cy="233.7" r=".46"/>
<circle cx="130.9" cy="176.9" r=".46"/>
<circle cx="92.8" cy="233.7" r=".46"/>
<circle cx="112.4" cy="211.8" r=".46"/>
<circle cx="76.3" cy="231.1" r=".46"/>
<circle cx="131.4" cy="236.2" r=".46"/>
<circle cx="131.4" cy="222.8" r=".46"/>
<circle cx="74.5" cy="50" r=".46"/>
<circle cx="74.3" cy="69.6" r=".46"/>
<circle cx="75.8" cy="171.8" r=".46"/>
<circle cx="224.8" cy="192.5" r=".46"/>
<circle cx="215.9" cy="177.3" r=".46"/>
<circle cx="243.8" cy="197.6" r=".46"/>
<circle cx="246.4" cy="197.6" r=".46"/>
<circle cx="224.8" cy="177.3" r=".46"/>
<circle cx="204.5" cy="187.5" r=".46"/>
<circle cx="111.9" cy="163.4" r=".46"/>
<circle cx="111.9" cy="152.5" r=".46"/>
<circle cx="130.9" cy="163.4" r=".46"/>
<circle cx="130.9" cy="168.1" r=".46"/>
<circle cx="92.3" cy="174.4" r=".46"/>
<circle cx="111.9" cy="174.4" r=".46"/>
<circle cx="293.4" cy="177.3" r=".46"/>
<circle cx="304.8" cy="177.3" r=".46"/>
<circle cx="327.7" cy="188.7" r=".46"/>
<circle cx="316.2" cy="177.3" r=".46"/>
<circle cx="327.7" cy="177.3" r=".46"/>
<circle cx="293.4" cy="188.7" r=".46"/>
<circle cx="316.2" cy="188.7" r=".46"/>
<circle cx="304.8" cy="188.7" r=".46"/>
<circle cx="339.1" cy="188.7" r=".46"/>
<circle cx="420" cy="221" r=".46"/>
<circle cx="404.5" cy="240" r=".46"/>
<circle cx="420" cy="224.8" r=".46"/>
<circle cx="339.1" cy="205.6" r=".46"/>
<circle cx="281.9" cy="177.3" r=".46"/>
<circle cx="281.9" cy="188.7" r=".46"/>
<circle cx="270.5" cy="177.3" r=".46"/>
<circle cx="261.6" cy="177.3" r=".46"/>
<circle cx="74.3" cy="329.2" r=".46"/>
<circle cx="62.5" cy="342.3" r=".46"/>
<circle cx="42.7" cy="329.2" r=".46"/>
<circle cx="83.4" cy="329.2" r=".46"/>
<circle cx="54.1" cy="329.2" r=".46"/>
<circle cx="40" cy="303.7" r=".46"/>
<circle cx="78.1" cy="329.2" r=".46"/>
<circle cx="61" cy="387.4" r=".46"/>
<circle cx="61" cy="392.4" r=".46"/>
<circle cx="63.5" cy="387.4" r=".46"/>
<circle cx="43.2" cy="387.4" r=".46"/>
<circle cx="61" cy="382.3" r=".46"/>
<circle cx="91.4" cy="387.4" r=".46"/>
<circle cx="91.4" cy="379.7" r=".46"/>
<circle cx="91.4" cy="395" r=".46"/>
<circle cx="124.2" cy="330.7" r=".46"/>
<circle cx="112.8" cy="330.7" r=".46"/>
<circle cx="144.4" cy="330.7" r=".46"/>
<circle cx="149.7" cy="330.7" r=".46"/>
<circle cx="132.6" cy="343.8" r=".46"/>
<circle cx="153.5" cy="330.7" r=".46"/>
<circle cx="146.6" cy="394.8" r=".46"/>
<circle cx="146.6" cy="376.6" r=".46"/>
<circle cx="157.1" cy="395" r=".46"/>
<circle cx="157.1" cy="387.4" r=".46"/>
<circle cx="162.1" cy="376.6" r=".46"/>
<circle cx="113" cy="387.4" r=".46"/>
<circle cx="102.7" cy="387.4" r=".46"/>
<circle cx="102.7" cy="379.7" r=".46"/>
<circle cx="102.7" cy="395" r=".46"/>
<circle cx="511" cy="334.8" r=".46"/>
<circle cx="526.3" cy="347.2" r=".46"/>
<circle cx="498.1" cy="349.8" r=".46"/>
<circle cx="446.7" cy="364.1" r=".46"/>
<circle cx="363" cy="363.5" r=".46"/>
<circle cx="446.7" cy="382.5" r=".46"/>
<circle cx="392.9" cy="365.4" r=".46"/>
<circle cx="420" cy="363.9" r=".46"/>
<circle cx="526" cy="290.2" r=".46"/>
<circle cx="510.8" cy="277.7" r=".46"/>
<circle cx="525.9" cy="233.3" r=".46"/>
<circle cx="409.6" cy="306.1" r=".46"/>
<circle cx="388" cy="316.2" r=".46"/>
<circle cx="409.6" cy="316.2" r=".46"/>
</g>
<use href="#words"/>
</svg>
